VERSION 5.7 ;
  NOWIREEXTENSIONATPIN ON ;
  DIVIDERCHAR "/" ;
  BUSBITCHARS "[]" ;
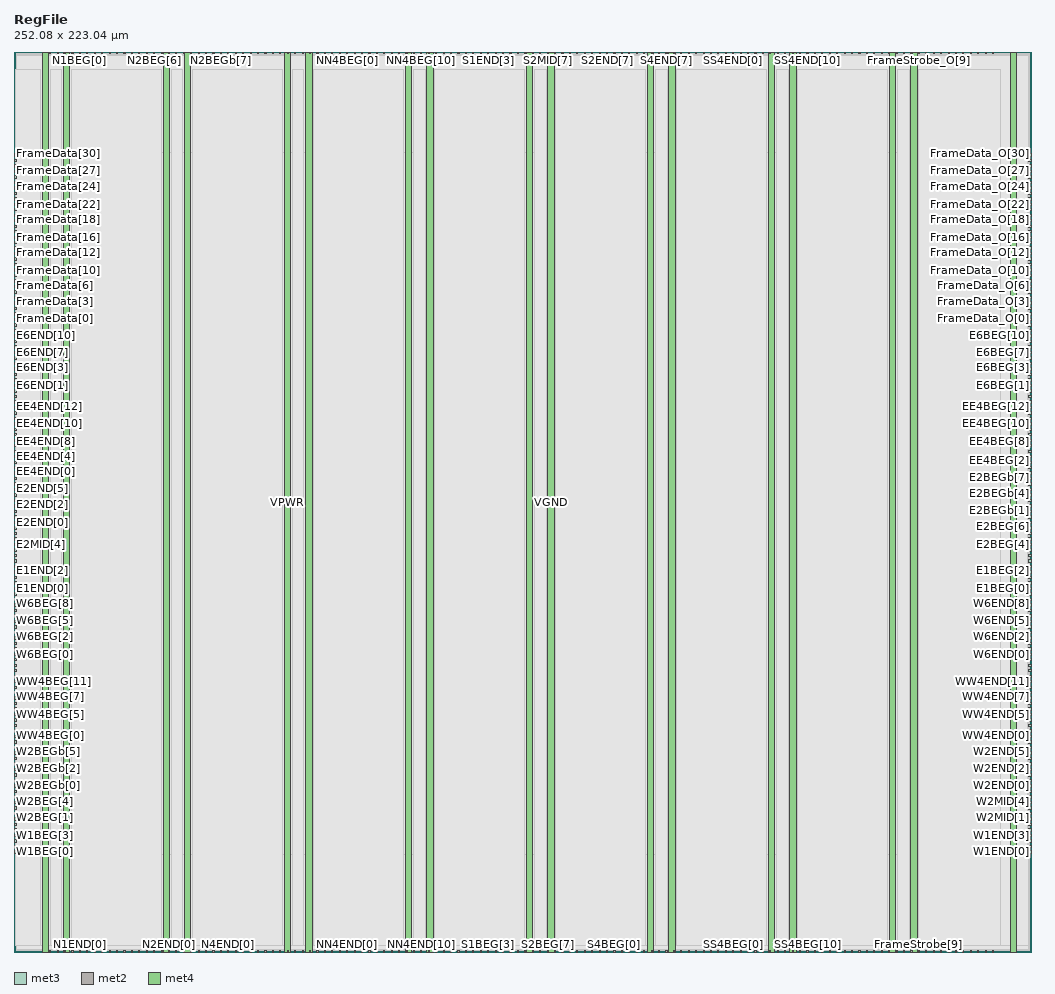
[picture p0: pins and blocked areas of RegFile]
MACRO RegFile
  CLASS BLOCK ;
  FOREIGN RegFile ;
  ORIGIN 0.000 0.000 ;
  SIZE 252.080 BY 223.040 ;
  PIN E1BEG[0]
    DIRECTION OUTPUT ;
    USE SIGNAL ;
    ANTENNADIFFAREA 0.702900 ;
    PORT
      LAYER met3 ;
        RECT 251.480 89.800 252.080 90.400 ;
    END
  END E1BEG[0]
  PIN E1BEG[1]
    DIRECTION OUTPUT ;
    USE SIGNAL ;
    ANTENNADIFFAREA 0.702900 ;
    PORT
      LAYER met3 ;
        RECT 251.480 91.160 252.080 91.760 ;
    END
  END E1BEG[1]
  PIN E1BEG[2]
    DIRECTION OUTPUT ;
    USE SIGNAL ;
    ANTENNADIFFAREA 0.702900 ;
    PORT
      LAYER met3 ;
        RECT 251.480 92.520 252.080 93.120 ;
    END
  END E1BEG[2]
  PIN E1BEG[3]
    DIRECTION OUTPUT ;
    USE SIGNAL ;
    ANTENNADIFFAREA 0.702900 ;
    PORT
      LAYER met3 ;
        RECT 251.480 93.880 252.080 94.480 ;
    END
  END E1BEG[3]
  PIN E1END[0]
    DIRECTION INPUT ;
    USE SIGNAL ;
    ANTENNAGATEAREA 1.398000 ;
    PORT
      LAYER met3 ;
        RECT 0.000 89.800 0.600 90.400 ;
    END
  END E1END[0]
  PIN E1END[1]
    DIRECTION INPUT ;
    USE SIGNAL ;
    ANTENNAGATEAREA 1.431000 ;
    PORT
      LAYER met3 ;
        RECT 0.000 91.160 0.600 91.760 ;
    END
  END E1END[1]
  PIN E1END[2]
    DIRECTION INPUT ;
    USE SIGNAL ;
    ANTENNAGATEAREA 2.117700 ;
    ANTENNADIFFAREA 0.434700 ;
    PORT
      LAYER met3 ;
        RECT 0.000 92.520 0.600 93.120 ;
    END
  END E1END[2]
  PIN E1END[3]
    DIRECTION INPUT ;
    USE SIGNAL ;
    ANTENNAGATEAREA 2.618400 ;
    ANTENNADIFFAREA 0.869400 ;
    PORT
      LAYER met3 ;
        RECT 0.000 93.880 0.600 94.480 ;
    END
  END E1END[3]
  PIN E2BEG[0]
    DIRECTION OUTPUT ;
    USE SIGNAL ;
    ANTENNADIFFAREA 0.702900 ;
    PORT
      LAYER met3 ;
        RECT 251.480 95.240 252.080 95.840 ;
    END
  END E2BEG[0]
  PIN E2BEG[1]
    DIRECTION OUTPUT ;
    USE SIGNAL ;
    ANTENNADIFFAREA 0.702900 ;
    PORT
      LAYER met3 ;
        RECT 251.480 96.600 252.080 97.200 ;
    END
  END E2BEG[1]
  PIN E2BEG[2]
    DIRECTION OUTPUT ;
    USE SIGNAL ;
    ANTENNADIFFAREA 0.702900 ;
    PORT
      LAYER met3 ;
        RECT 251.480 97.960 252.080 98.560 ;
    END
  END E2BEG[2]
  PIN E2BEG[3]
    DIRECTION OUTPUT ;
    USE SIGNAL ;
    ANTENNADIFFAREA 0.702900 ;
    PORT
      LAYER met3 ;
        RECT 251.480 99.320 252.080 99.920 ;
    END
  END E2BEG[3]
  PIN E2BEG[4]
    DIRECTION OUTPUT ;
    USE SIGNAL ;
    ANTENNADIFFAREA 0.702900 ;
    PORT
      LAYER met3 ;
        RECT 251.480 100.680 252.080 101.280 ;
    END
  END E2BEG[4]
  PIN E2BEG[5]
    DIRECTION OUTPUT ;
    USE SIGNAL ;
    ANTENNADIFFAREA 0.702900 ;
    PORT
      LAYER met3 ;
        RECT 251.480 102.040 252.080 102.640 ;
    END
  END E2BEG[5]
  PIN E2BEG[6]
    DIRECTION OUTPUT ;
    USE SIGNAL ;
    ANTENNADIFFAREA 0.702900 ;
    PORT
      LAYER met3 ;
        RECT 251.480 103.400 252.080 104.000 ;
    END
  END E2BEG[6]
  PIN E2BEG[7]
    DIRECTION OUTPUT ;
    USE SIGNAL ;
    ANTENNADIFFAREA 0.702900 ;
    PORT
      LAYER met3 ;
        RECT 251.480 104.760 252.080 105.360 ;
    END
  END E2BEG[7]
  PIN E2BEGb[0]
    DIRECTION OUTPUT ;
    USE SIGNAL ;
    ANTENNADIFFAREA 0.702900 ;
    PORT
      LAYER met3 ;
        RECT 251.480 106.120 252.080 106.720 ;
    END
  END E2BEGb[0]
  PIN E2BEGb[1]
    DIRECTION OUTPUT ;
    USE SIGNAL ;
    ANTENNADIFFAREA 0.702900 ;
    PORT
      LAYER met3 ;
        RECT 251.480 107.480 252.080 108.080 ;
    END
  END E2BEGb[1]
  PIN E2BEGb[2]
    DIRECTION OUTPUT ;
    USE SIGNAL ;
    ANTENNADIFFAREA 0.702900 ;
    PORT
      LAYER met3 ;
        RECT 251.480 108.840 252.080 109.440 ;
    END
  END E2BEGb[2]
  PIN E2BEGb[3]
    DIRECTION OUTPUT ;
    USE SIGNAL ;
    ANTENNADIFFAREA 0.702900 ;
    PORT
      LAYER met3 ;
        RECT 251.480 110.200 252.080 110.800 ;
    END
  END E2BEGb[3]
  PIN E2BEGb[4]
    DIRECTION OUTPUT ;
    USE SIGNAL ;
    ANTENNADIFFAREA 0.702900 ;
    PORT
      LAYER met3 ;
        RECT 251.480 111.560 252.080 112.160 ;
    END
  END E2BEGb[4]
  PIN E2BEGb[5]
    DIRECTION OUTPUT ;
    USE SIGNAL ;
    ANTENNADIFFAREA 0.702900 ;
    PORT
      LAYER met3 ;
        RECT 251.480 112.920 252.080 113.520 ;
    END
  END E2BEGb[5]
  PIN E2BEGb[6]
    DIRECTION OUTPUT ;
    USE SIGNAL ;
    ANTENNADIFFAREA 0.702900 ;
    PORT
      LAYER met3 ;
        RECT 251.480 114.280 252.080 114.880 ;
    END
  END E2BEGb[6]
  PIN E2BEGb[7]
    DIRECTION OUTPUT ;
    USE SIGNAL ;
    ANTENNADIFFAREA 0.702900 ;
    PORT
      LAYER met3 ;
        RECT 251.480 115.640 252.080 116.240 ;
    END
  END E2BEGb[7]
  PIN E2END[0]
    DIRECTION INPUT ;
    USE SIGNAL ;
    ANTENNAGATEAREA 1.664400 ;
    ANTENNADIFFAREA 0.869400 ;
    PORT
      LAYER met3 ;
        RECT 0.000 106.120 0.600 106.720 ;
    END
  END E2END[0]
  PIN E2END[1]
    DIRECTION INPUT ;
    USE SIGNAL ;
    ANTENNAGATEAREA 0.795000 ;
    PORT
      LAYER met3 ;
        RECT 0.000 107.480 0.600 108.080 ;
    END
  END E2END[1]
  PIN E2END[2]
    DIRECTION INPUT ;
    USE SIGNAL ;
    ANTENNAGATEAREA 2.108400 ;
    ANTENNADIFFAREA 0.869400 ;
    PORT
      LAYER met3 ;
        RECT 0.000 108.840 0.600 109.440 ;
    END
  END E2END[2]
  PIN E2END[3]
    DIRECTION INPUT ;
    USE SIGNAL ;
    ANTENNAGATEAREA 1.272000 ;
    PORT
      LAYER met3 ;
        RECT 0.000 110.200 0.600 110.800 ;
    END
  END E2END[3]
  PIN E2END[4]
    DIRECTION INPUT ;
    USE SIGNAL ;
    ANTENNAGATEAREA 0.795000 ;
    PORT
      LAYER met3 ;
        RECT 0.000 111.560 0.600 112.160 ;
    END
  END E2END[4]
  PIN E2END[5]
    DIRECTION INPUT ;
    USE SIGNAL ;
    ANTENNAGATEAREA 0.954000 ;
    PORT
      LAYER met3 ;
        RECT 0.000 112.920 0.600 113.520 ;
    END
  END E2END[5]
  PIN E2END[6]
    DIRECTION INPUT ;
    USE SIGNAL ;
    ANTENNAGATEAREA 1.823400 ;
    ANTENNADIFFAREA 0.869400 ;
    PORT
      LAYER met3 ;
        RECT 0.000 114.280 0.600 114.880 ;
    END
  END E2END[6]
  PIN E2END[7]
    DIRECTION INPUT ;
    USE SIGNAL ;
    ANTENNAGATEAREA 1.664400 ;
    ANTENNADIFFAREA 0.869400 ;
    PORT
      LAYER met3 ;
        RECT 0.000 115.640 0.600 116.240 ;
    END
  END E2END[7]
  PIN E2MID[0]
    DIRECTION INPUT ;
    USE SIGNAL ;
    ANTENNAGATEAREA 1.907100 ;
    ANTENNADIFFAREA 1.304100 ;
    PORT
      LAYER met3 ;
        RECT 0.000 95.240 0.600 95.840 ;
    END
  END E2MID[0]
  PIN E2MID[1]
    DIRECTION INPUT ;
    USE SIGNAL ;
    ANTENNAGATEAREA 0.696000 ;
    PORT
      LAYER met3 ;
        RECT 0.000 96.600 0.600 97.200 ;
    END
  END E2MID[1]
  PIN E2MID[2]
    DIRECTION INPUT ;
    USE SIGNAL ;
    ANTENNAGATEAREA 0.724500 ;
    PORT
      LAYER met3 ;
        RECT 0.000 97.960 0.600 98.560 ;
    END
  END E2MID[2]
  PIN E2MID[3]
    DIRECTION INPUT ;
    USE SIGNAL ;
    ANTENNAGATEAREA 1.229700 ;
    ANTENNADIFFAREA 0.434700 ;
    PORT
      LAYER met3 ;
        RECT 0.000 99.320 0.600 99.920 ;
    END
  END E2MID[3]
  PIN E2MID[4]
    DIRECTION INPUT ;
    USE SIGNAL ;
    ANTENNAGATEAREA 2.374800 ;
    ANTENNADIFFAREA 1.738800 ;
    PORT
      LAYER met3 ;
        RECT 0.000 100.680 0.600 101.280 ;
    END
  END E2MID[4]
  PIN E2MID[5]
    DIRECTION INPUT ;
    USE SIGNAL ;
    ANTENNAGATEAREA 2.968500 ;
    ANTENNADIFFAREA 2.173500 ;
    PORT
      LAYER met3 ;
        RECT 0.000 102.040 0.600 102.640 ;
    END
  END E2MID[5]
  PIN E2MID[6]
    DIRECTION INPUT ;
    USE SIGNAL ;
    ANTENNAGATEAREA 1.439400 ;
    ANTENNADIFFAREA 0.869400 ;
    PORT
      LAYER met3 ;
        RECT 0.000 103.400 0.600 104.000 ;
    END
  END E2MID[6]
  PIN E2MID[7]
    DIRECTION INPUT ;
    USE SIGNAL ;
    ANTENNAGATEAREA 2.869500 ;
    ANTENNADIFFAREA 2.173500 ;
    PORT
      LAYER met3 ;
        RECT 0.000 104.760 0.600 105.360 ;
    END
  END E2MID[7]
  PIN E6BEG[0]
    DIRECTION OUTPUT ;
    USE SIGNAL ;
    ANTENNADIFFAREA 0.702900 ;
    PORT
      LAYER met3 ;
        RECT 251.480 138.760 252.080 139.360 ;
    END
  END E6BEG[0]
  PIN E6BEG[10]
    DIRECTION OUTPUT ;
    USE SIGNAL ;
    ANTENNADIFFAREA 0.702900 ;
    PORT
      LAYER met3 ;
        RECT 251.480 152.360 252.080 152.960 ;
    END
  END E6BEG[10]
  PIN E6BEG[11]
    DIRECTION OUTPUT ;
    USE SIGNAL ;
    ANTENNADIFFAREA 0.702900 ;
    PORT
      LAYER met3 ;
        RECT 251.480 153.720 252.080 154.320 ;
    END
  END E6BEG[11]
  PIN E6BEG[1]
    DIRECTION OUTPUT ;
    USE SIGNAL ;
    ANTENNADIFFAREA 0.702900 ;
    PORT
      LAYER met3 ;
        RECT 251.480 140.120 252.080 140.720 ;
    END
  END E6BEG[1]
  PIN E6BEG[2]
    DIRECTION OUTPUT ;
    USE SIGNAL ;
    ANTENNADIFFAREA 0.702900 ;
    PORT
      LAYER met3 ;
        RECT 251.480 141.480 252.080 142.080 ;
    END
  END E6BEG[2]
  PIN E6BEG[3]
    DIRECTION OUTPUT ;
    USE SIGNAL ;
    ANTENNADIFFAREA 0.702900 ;
    PORT
      LAYER met3 ;
        RECT 251.480 142.840 252.080 143.440 ;
    END
  END E6BEG[3]
  PIN E6BEG[4]
    DIRECTION OUTPUT ;
    USE SIGNAL ;
    ANTENNADIFFAREA 0.702900 ;
    PORT
      LAYER met3 ;
        RECT 251.480 144.200 252.080 144.800 ;
    END
  END E6BEG[4]
  PIN E6BEG[5]
    DIRECTION OUTPUT ;
    USE SIGNAL ;
    ANTENNADIFFAREA 0.702900 ;
    PORT
      LAYER met3 ;
        RECT 251.480 145.560 252.080 146.160 ;
    END
  END E6BEG[5]
  PIN E6BEG[6]
    DIRECTION OUTPUT ;
    USE SIGNAL ;
    ANTENNADIFFAREA 0.702900 ;
    PORT
      LAYER met3 ;
        RECT 251.480 146.920 252.080 147.520 ;
    END
  END E6BEG[6]
  PIN E6BEG[7]
    DIRECTION OUTPUT ;
    USE SIGNAL ;
    ANTENNADIFFAREA 0.702900 ;
    PORT
      LAYER met3 ;
        RECT 251.480 148.280 252.080 148.880 ;
    END
  END E6BEG[7]
  PIN E6BEG[8]
    DIRECTION OUTPUT ;
    USE SIGNAL ;
    ANTENNADIFFAREA 0.702900 ;
    PORT
      LAYER met3 ;
        RECT 251.480 149.640 252.080 150.240 ;
    END
  END E6BEG[8]
  PIN E6BEG[9]
    DIRECTION OUTPUT ;
    USE SIGNAL ;
    ANTENNADIFFAREA 0.702900 ;
    PORT
      LAYER met3 ;
        RECT 251.480 151.000 252.080 151.600 ;
    END
  END E6BEG[9]
  PIN E6END[0]
    DIRECTION INPUT ;
    USE SIGNAL ;
    ANTENNAGATEAREA 1.875000 ;
    PORT
      LAYER met3 ;
        RECT 0.000 138.760 0.600 139.360 ;
    END
  END E6END[0]
  PIN E6END[10]
    DIRECTION INPUT ;
    USE SIGNAL ;
    ANTENNAGATEAREA 0.159000 ;
    PORT
      LAYER met3 ;
        RECT 0.000 152.360 0.600 152.960 ;
    END
  END E6END[10]
  PIN E6END[11]
    DIRECTION INPUT ;
    USE SIGNAL ;
    ANTENNAGATEAREA 0.159000 ;
    PORT
      LAYER met3 ;
        RECT 0.000 153.720 0.600 154.320 ;
    END
  END E6END[11]
  PIN E6END[1]
    DIRECTION INPUT ;
    USE SIGNAL ;
    ANTENNAGATEAREA 1.875000 ;
    PORT
      LAYER met3 ;
        RECT 0.000 140.120 0.600 140.720 ;
    END
  END E6END[1]
  PIN E6END[2]
    DIRECTION INPUT ;
    USE SIGNAL ;
    ANTENNAGATEAREA 0.159000 ;
    PORT
      LAYER met3 ;
        RECT 0.000 141.480 0.600 142.080 ;
    END
  END E6END[2]
  PIN E6END[3]
    DIRECTION INPUT ;
    USE SIGNAL ;
    ANTENNAGATEAREA 0.159000 ;
    PORT
      LAYER met3 ;
        RECT 0.000 142.840 0.600 143.440 ;
    END
  END E6END[3]
  PIN E6END[4]
    DIRECTION INPUT ;
    USE SIGNAL ;
    ANTENNAGATEAREA 0.159000 ;
    PORT
      LAYER met3 ;
        RECT 0.000 144.200 0.600 144.800 ;
    END
  END E6END[4]
  PIN E6END[5]
    DIRECTION INPUT ;
    USE SIGNAL ;
    ANTENNAGATEAREA 0.159000 ;
    PORT
      LAYER met3 ;
        RECT 0.000 145.560 0.600 146.160 ;
    END
  END E6END[5]
  PIN E6END[6]
    DIRECTION INPUT ;
    USE SIGNAL ;
    ANTENNAGATEAREA 0.159000 ;
    PORT
      LAYER met3 ;
        RECT 0.000 146.920 0.600 147.520 ;
    END
  END E6END[6]
  PIN E6END[7]
    DIRECTION INPUT ;
    USE SIGNAL ;
    ANTENNAGATEAREA 0.159000 ;
    PORT
      LAYER met3 ;
        RECT 0.000 148.280 0.600 148.880 ;
    END
  END E6END[7]
  PIN E6END[8]
    DIRECTION INPUT ;
    USE SIGNAL ;
    ANTENNAGATEAREA 0.159000 ;
    PORT
      LAYER met3 ;
        RECT 0.000 149.640 0.600 150.240 ;
    END
  END E6END[8]
  PIN E6END[9]
    DIRECTION INPUT ;
    USE SIGNAL ;
    ANTENNAGATEAREA 0.159000 ;
    PORT
      LAYER met3 ;
        RECT 0.000 151.000 0.600 151.600 ;
    END
  END E6END[9]
  PIN EE4BEG[0]
    DIRECTION OUTPUT ;
    USE SIGNAL ;
    ANTENNADIFFAREA 0.702900 ;
    PORT
      LAYER met3 ;
        RECT 251.480 117.000 252.080 117.600 ;
    END
  END EE4BEG[0]
  PIN EE4BEG[10]
    DIRECTION OUTPUT ;
    USE SIGNAL ;
    ANTENNADIFFAREA 0.702900 ;
    PORT
      LAYER met3 ;
        RECT 251.480 130.600 252.080 131.200 ;
    END
  END EE4BEG[10]
  PIN EE4BEG[11]
    DIRECTION OUTPUT ;
    USE SIGNAL ;
    ANTENNADIFFAREA 0.702900 ;
    PORT
      LAYER met3 ;
        RECT 251.480 131.960 252.080 132.560 ;
    END
  END EE4BEG[11]
  PIN EE4BEG[12]
    DIRECTION OUTPUT ;
    USE SIGNAL ;
    ANTENNADIFFAREA 0.702900 ;
    PORT
      LAYER met3 ;
        RECT 251.480 133.320 252.080 133.920 ;
    END
  END EE4BEG[12]
  PIN EE4BEG[13]
    DIRECTION OUTPUT ;
    USE SIGNAL ;
    ANTENNADIFFAREA 0.702900 ;
    PORT
      LAYER met3 ;
        RECT 251.480 134.680 252.080 135.280 ;
    END
  END EE4BEG[13]
  PIN EE4BEG[14]
    DIRECTION OUTPUT ;
    USE SIGNAL ;
    ANTENNADIFFAREA 0.702900 ;
    PORT
      LAYER met3 ;
        RECT 251.480 136.040 252.080 136.640 ;
    END
  END EE4BEG[14]
  PIN EE4BEG[15]
    DIRECTION OUTPUT ;
    USE SIGNAL ;
    ANTENNADIFFAREA 0.702900 ;
    PORT
      LAYER met3 ;
        RECT 251.480 137.400 252.080 138.000 ;
    END
  END EE4BEG[15]
  PIN EE4BEG[1]
    DIRECTION OUTPUT ;
    USE SIGNAL ;
    ANTENNADIFFAREA 0.702900 ;
    PORT
      LAYER met3 ;
        RECT 251.480 118.360 252.080 118.960 ;
    END
  END EE4BEG[1]
  PIN EE4BEG[2]
    DIRECTION OUTPUT ;
    USE SIGNAL ;
    ANTENNADIFFAREA 0.702900 ;
    PORT
      LAYER met3 ;
        RECT 251.480 119.720 252.080 120.320 ;
    END
  END EE4BEG[2]
  PIN EE4BEG[3]
    DIRECTION OUTPUT ;
    USE SIGNAL ;
    ANTENNADIFFAREA 0.702900 ;
    PORT
      LAYER met3 ;
        RECT 251.480 121.080 252.080 121.680 ;
    END
  END EE4BEG[3]
  PIN EE4BEG[4]
    DIRECTION OUTPUT ;
    USE SIGNAL ;
    ANTENNADIFFAREA 0.702900 ;
    PORT
      LAYER met3 ;
        RECT 251.480 122.440 252.080 123.040 ;
    END
  END EE4BEG[4]
  PIN EE4BEG[5]
    DIRECTION OUTPUT ;
    USE SIGNAL ;
    ANTENNADIFFAREA 0.702900 ;
    PORT
      LAYER met3 ;
        RECT 251.480 123.800 252.080 124.400 ;
    END
  END EE4BEG[5]
  PIN EE4BEG[6]
    DIRECTION OUTPUT ;
    USE SIGNAL ;
    ANTENNADIFFAREA 0.702900 ;
    PORT
      LAYER met3 ;
        RECT 251.480 125.160 252.080 125.760 ;
    END
  END EE4BEG[6]
  PIN EE4BEG[7]
    DIRECTION OUTPUT ;
    USE SIGNAL ;
    ANTENNADIFFAREA 0.702900 ;
    PORT
      LAYER met3 ;
        RECT 251.480 126.520 252.080 127.120 ;
    END
  END EE4BEG[7]
  PIN EE4BEG[8]
    DIRECTION OUTPUT ;
    USE SIGNAL ;
    ANTENNADIFFAREA 0.702900 ;
    PORT
      LAYER met3 ;
        RECT 251.480 127.880 252.080 128.480 ;
    END
  END EE4BEG[8]
  PIN EE4BEG[9]
    DIRECTION OUTPUT ;
    USE SIGNAL ;
    ANTENNADIFFAREA 0.702900 ;
    PORT
      LAYER met3 ;
        RECT 251.480 129.240 252.080 129.840 ;
    END
  END EE4BEG[9]
  PIN EE4END[0]
    DIRECTION INPUT ;
    USE SIGNAL ;
    ANTENNAGATEAREA 2.374800 ;
    ANTENNADIFFAREA 1.738800 ;
    PORT
      LAYER met3 ;
        RECT 0.000 117.000 0.600 117.600 ;
    END
  END EE4END[0]
  PIN EE4END[10]
    DIRECTION INPUT ;
    USE SIGNAL ;
    ANTENNAGATEAREA 0.159000 ;
    PORT
      LAYER met3 ;
        RECT 0.000 130.600 0.600 131.200 ;
    END
  END EE4END[10]
  PIN EE4END[11]
    DIRECTION INPUT ;
    USE SIGNAL ;
    ANTENNAGATEAREA 0.159000 ;
    PORT
      LAYER met3 ;
        RECT 0.000 131.960 0.600 132.560 ;
    END
  END EE4END[11]
  PIN EE4END[12]
    DIRECTION INPUT ;
    USE SIGNAL ;
    ANTENNAGATEAREA 0.159000 ;
    PORT
      LAYER met3 ;
        RECT 0.000 133.320 0.600 133.920 ;
    END
  END EE4END[12]
  PIN EE4END[13]
    DIRECTION INPUT ;
    USE SIGNAL ;
    ANTENNAGATEAREA 0.159000 ;
    PORT
      LAYER met3 ;
        RECT 0.000 134.680 0.600 135.280 ;
    END
  END EE4END[13]
  PIN EE4END[14]
    DIRECTION INPUT ;
    USE SIGNAL ;
    ANTENNAGATEAREA 0.159000 ;
    PORT
      LAYER met3 ;
        RECT 0.000 136.040 0.600 136.640 ;
    END
  END EE4END[14]
  PIN EE4END[15]
    DIRECTION INPUT ;
    USE SIGNAL ;
    ANTENNAGATEAREA 0.159000 ;
    PORT
      LAYER met3 ;
        RECT 0.000 137.400 0.600 138.000 ;
    END
  END EE4END[15]
  PIN EE4END[1]
    DIRECTION INPUT ;
    USE SIGNAL ;
    ANTENNAGATEAREA 1.505400 ;
    ANTENNADIFFAREA 0.869400 ;
    PORT
      LAYER met3 ;
        RECT 0.000 118.360 0.600 118.960 ;
    END
  END EE4END[1]
  PIN EE4END[2]
    DIRECTION INPUT ;
    USE SIGNAL ;
    ANTENNAGATEAREA 1.070700 ;
    ANTENNADIFFAREA 0.434700 ;
    PORT
      LAYER met3 ;
        RECT 0.000 119.720 0.600 120.320 ;
    END
  END EE4END[2]
  PIN EE4END[3]
    DIRECTION INPUT ;
    USE SIGNAL ;
    ANTENNAGATEAREA 1.406700 ;
    ANTENNADIFFAREA 0.434700 ;
    PORT
      LAYER met3 ;
        RECT 0.000 121.080 0.600 121.680 ;
    END
  END EE4END[3]
  PIN EE4END[4]
    DIRECTION INPUT ;
    USE SIGNAL ;
    ANTENNAGATEAREA 0.159000 ;
    PORT
      LAYER met3 ;
        RECT 0.000 122.440 0.600 123.040 ;
    END
  END EE4END[4]
  PIN EE4END[5]
    DIRECTION INPUT ;
    USE SIGNAL ;
    ANTENNAGATEAREA 0.159000 ;
    PORT
      LAYER met3 ;
        RECT 0.000 123.800 0.600 124.400 ;
    END
  END EE4END[5]
  PIN EE4END[6]
    DIRECTION INPUT ;
    USE SIGNAL ;
    ANTENNAGATEAREA 0.159000 ;
    PORT
      LAYER met3 ;
        RECT 0.000 125.160 0.600 125.760 ;
    END
  END EE4END[6]
  PIN EE4END[7]
    DIRECTION INPUT ;
    USE SIGNAL ;
    ANTENNAGATEAREA 0.159000 ;
    PORT
      LAYER met3 ;
        RECT 0.000 126.520 0.600 127.120 ;
    END
  END EE4END[7]
  PIN EE4END[8]
    DIRECTION INPUT ;
    USE SIGNAL ;
    ANTENNAGATEAREA 0.159000 ;
    PORT
      LAYER met3 ;
        RECT 0.000 127.880 0.600 128.480 ;
    END
  END EE4END[8]
  PIN EE4END[9]
    DIRECTION INPUT ;
    USE SIGNAL ;
    ANTENNAGATEAREA 0.159000 ;
    PORT
      LAYER met3 ;
        RECT 0.000 129.240 0.600 129.840 ;
    END
  END EE4END[9]
  PIN FrameData[0]
    DIRECTION INPUT ;
    USE SIGNAL ;
    ANTENNAGATEAREA 2.660700 ;
    ANTENNADIFFAREA 0.434700 ;
    PORT
      LAYER met3 ;
        RECT 0.000 155.080 0.600 155.680 ;
    END
  END FrameData[0]
  PIN FrameData[10]
    DIRECTION INPUT ;
    USE SIGNAL ;
    ANTENNAGATEAREA 2.660700 ;
    ANTENNADIFFAREA 0.434700 ;
    PORT
      LAYER met3 ;
        RECT 0.000 168.680 0.600 169.280 ;
    END
  END FrameData[10]
  PIN FrameData[11]
    DIRECTION INPUT ;
    USE SIGNAL ;
    ANTENNAGATEAREA 2.660700 ;
    ANTENNADIFFAREA 0.434700 ;
    PORT
      LAYER met3 ;
        RECT 0.000 170.040 0.600 170.640 ;
    END
  END FrameData[11]
  PIN FrameData[12]
    DIRECTION INPUT ;
    USE SIGNAL ;
    ANTENNAGATEAREA 2.226000 ;
    PORT
      LAYER met3 ;
        RECT 0.000 171.400 0.600 172.000 ;
    END
  END FrameData[12]
  PIN FrameData[13]
    DIRECTION INPUT ;
    USE SIGNAL ;
    ANTENNAGATEAREA 2.226000 ;
    PORT
      LAYER met3 ;
        RECT 0.000 172.760 0.600 173.360 ;
    END
  END FrameData[13]
  PIN FrameData[14]
    DIRECTION INPUT ;
    USE SIGNAL ;
    ANTENNAGATEAREA 2.226000 ;
    PORT
      LAYER met3 ;
        RECT 0.000 174.120 0.600 174.720 ;
    END
  END FrameData[14]
  PIN FrameData[15]
    DIRECTION INPUT ;
    USE SIGNAL ;
    ANTENNAGATEAREA 2.226000 ;
    PORT
      LAYER met3 ;
        RECT 0.000 175.480 0.600 176.080 ;
    END
  END FrameData[15]
  PIN FrameData[16]
    DIRECTION INPUT ;
    USE SIGNAL ;
    ANTENNAGATEAREA 2.226000 ;
    PORT
      LAYER met3 ;
        RECT 0.000 176.840 0.600 177.440 ;
    END
  END FrameData[16]
  PIN FrameData[17]
    DIRECTION INPUT ;
    USE SIGNAL ;
    ANTENNAGATEAREA 2.226000 ;
    PORT
      LAYER met3 ;
        RECT 0.000 178.200 0.600 178.800 ;
    END
  END FrameData[17]
  PIN FrameData[18]
    DIRECTION INPUT ;
    USE SIGNAL ;
    ANTENNAGATEAREA 2.226000 ;
    PORT
      LAYER met3 ;
        RECT 0.000 179.560 0.600 180.160 ;
    END
  END FrameData[18]
  PIN FrameData[19]
    DIRECTION INPUT ;
    USE SIGNAL ;
    ANTENNAGATEAREA 2.385000 ;
    PORT
      LAYER met3 ;
        RECT 0.000 180.920 0.600 181.520 ;
    END
  END FrameData[19]
  PIN FrameData[1]
    DIRECTION INPUT ;
    USE SIGNAL ;
    ANTENNAGATEAREA 2.226000 ;
    PORT
      LAYER met3 ;
        RECT 0.000 156.440 0.600 157.040 ;
    END
  END FrameData[1]
  PIN FrameData[20]
    DIRECTION INPUT ;
    USE SIGNAL ;
    ANTENNAGATEAREA 2.385000 ;
    PORT
      LAYER met3 ;
        RECT 0.000 182.280 0.600 182.880 ;
    END
  END FrameData[20]
  PIN FrameData[21]
    DIRECTION INPUT ;
    USE SIGNAL ;
    ANTENNAGATEAREA 2.385000 ;
    PORT
      LAYER met3 ;
        RECT 0.000 183.640 0.600 184.240 ;
    END
  END FrameData[21]
  PIN FrameData[22]
    DIRECTION INPUT ;
    USE SIGNAL ;
    ANTENNAGATEAREA 4.558500 ;
    ANTENNADIFFAREA 2.173500 ;
    PORT
      LAYER met3 ;
        RECT 0.000 185.000 0.600 185.600 ;
    END
  END FrameData[22]
  PIN FrameData[23]
    DIRECTION INPUT ;
    USE SIGNAL ;
    ANTENNAGATEAREA 2.385000 ;
    PORT
      LAYER met3 ;
        RECT 0.000 186.360 0.600 186.960 ;
    END
  END FrameData[23]
  PIN FrameData[24]
    DIRECTION INPUT ;
    USE SIGNAL ;
    ANTENNAGATEAREA 2.385000 ;
    PORT
      LAYER met3 ;
        RECT 0.000 187.720 0.600 188.320 ;
    END
  END FrameData[24]
  PIN FrameData[25]
    DIRECTION INPUT ;
    USE SIGNAL ;
    ANTENNAGATEAREA 2.385000 ;
    PORT
      LAYER met3 ;
        RECT 0.000 189.080 0.600 189.680 ;
    END
  END FrameData[25]
  PIN FrameData[26]
    DIRECTION INPUT ;
    USE SIGNAL ;
    ANTENNAGATEAREA 2.385000 ;
    PORT
      LAYER met3 ;
        RECT 0.000 190.440 0.600 191.040 ;
    END
  END FrameData[26]
  PIN FrameData[27]
    DIRECTION INPUT ;
    USE SIGNAL ;
    ANTENNAGATEAREA 2.385000 ;
    PORT
      LAYER met3 ;
        RECT 0.000 191.800 0.600 192.400 ;
    END
  END FrameData[27]
  PIN FrameData[28]
    DIRECTION INPUT ;
    USE SIGNAL ;
    ANTENNAGATEAREA 2.819700 ;
    ANTENNADIFFAREA 0.434700 ;
    PORT
      LAYER met3 ;
        RECT 0.000 193.160 0.600 193.760 ;
    END
  END FrameData[28]
  PIN FrameData[29]
    DIRECTION INPUT ;
    USE SIGNAL ;
    ANTENNAGATEAREA 2.385000 ;
    PORT
      LAYER met3 ;
        RECT 0.000 194.520 0.600 195.120 ;
    END
  END FrameData[29]
  PIN FrameData[2]
    DIRECTION INPUT ;
    USE SIGNAL ;
    ANTENNAGATEAREA 2.226000 ;
    PORT
      LAYER met3 ;
        RECT 0.000 157.800 0.600 158.400 ;
    END
  END FrameData[2]
  PIN FrameData[30]
    DIRECTION INPUT ;
    USE SIGNAL ;
    ANTENNAGATEAREA 2.385000 ;
    PORT
      LAYER met3 ;
        RECT 0.000 195.880 0.600 196.480 ;
    END
  END FrameData[30]
  PIN FrameData[31]
    DIRECTION INPUT ;
    USE SIGNAL ;
    ANTENNAGATEAREA 2.385000 ;
    PORT
      LAYER met3 ;
        RECT 0.000 197.240 0.600 197.840 ;
    END
  END FrameData[31]
  PIN FrameData[3]
    DIRECTION INPUT ;
    USE SIGNAL ;
    ANTENNAGATEAREA 2.226000 ;
    PORT
      LAYER met3 ;
        RECT 0.000 159.160 0.600 159.760 ;
    END
  END FrameData[3]
  PIN FrameData[4]
    DIRECTION INPUT ;
    USE SIGNAL ;
    ANTENNAGATEAREA 2.226000 ;
    PORT
      LAYER met3 ;
        RECT 0.000 160.520 0.600 161.120 ;
    END
  END FrameData[4]
  PIN FrameData[5]
    DIRECTION INPUT ;
    USE SIGNAL ;
    ANTENNAGATEAREA 2.226000 ;
    PORT
      LAYER met3 ;
        RECT 0.000 161.880 0.600 162.480 ;
    END
  END FrameData[5]
  PIN FrameData[6]
    DIRECTION INPUT ;
    USE SIGNAL ;
    ANTENNAGATEAREA 2.226000 ;
    PORT
      LAYER met3 ;
        RECT 0.000 163.240 0.600 163.840 ;
    END
  END FrameData[6]
  PIN FrameData[7]
    DIRECTION INPUT ;
    USE SIGNAL ;
    ANTENNAGATEAREA 2.226000 ;
    PORT
      LAYER met3 ;
        RECT 0.000 164.600 0.600 165.200 ;
    END
  END FrameData[7]
  PIN FrameData[8]
    DIRECTION INPUT ;
    USE SIGNAL ;
    ANTENNAGATEAREA 2.226000 ;
    PORT
      LAYER met3 ;
        RECT 0.000 165.960 0.600 166.560 ;
    END
  END FrameData[8]
  PIN FrameData[9]
    DIRECTION INPUT ;
    USE SIGNAL ;
    ANTENNAGATEAREA 2.226000 ;
    PORT
      LAYER met3 ;
        RECT 0.000 167.320 0.600 167.920 ;
    END
  END FrameData[9]
  PIN FrameData_O[0]
    DIRECTION OUTPUT ;
    USE SIGNAL ;
    ANTENNADIFFAREA 0.702900 ;
    PORT
      LAYER met3 ;
        RECT 251.480 155.080 252.080 155.680 ;
    END
  END FrameData_O[0]
  PIN FrameData_O[10]
    DIRECTION OUTPUT ;
    USE SIGNAL ;
    ANTENNADIFFAREA 0.702900 ;
    PORT
      LAYER met3 ;
        RECT 251.480 168.680 252.080 169.280 ;
    END
  END FrameData_O[10]
  PIN FrameData_O[11]
    DIRECTION OUTPUT ;
    USE SIGNAL ;
    ANTENNADIFFAREA 0.702900 ;
    PORT
      LAYER met3 ;
        RECT 251.480 170.040 252.080 170.640 ;
    END
  END FrameData_O[11]
  PIN FrameData_O[12]
    DIRECTION OUTPUT ;
    USE SIGNAL ;
    ANTENNADIFFAREA 0.702900 ;
    PORT
      LAYER met3 ;
        RECT 251.480 171.400 252.080 172.000 ;
    END
  END FrameData_O[12]
  PIN FrameData_O[13]
    DIRECTION OUTPUT ;
    USE SIGNAL ;
    ANTENNADIFFAREA 0.702900 ;
    PORT
      LAYER met3 ;
        RECT 251.480 172.760 252.080 173.360 ;
    END
  END FrameData_O[13]
  PIN FrameData_O[14]
    DIRECTION OUTPUT ;
    USE SIGNAL ;
    ANTENNADIFFAREA 0.702900 ;
    PORT
      LAYER met3 ;
        RECT 251.480 174.120 252.080 174.720 ;
    END
  END FrameData_O[14]
  PIN FrameData_O[15]
    DIRECTION OUTPUT ;
    USE SIGNAL ;
    ANTENNADIFFAREA 0.702900 ;
    PORT
      LAYER met3 ;
        RECT 251.480 175.480 252.080 176.080 ;
    END
  END FrameData_O[15]
  PIN FrameData_O[16]
    DIRECTION OUTPUT ;
    USE SIGNAL ;
    ANTENNADIFFAREA 0.702900 ;
    PORT
      LAYER met3 ;
        RECT 251.480 176.840 252.080 177.440 ;
    END
  END FrameData_O[16]
  PIN FrameData_O[17]
    DIRECTION OUTPUT ;
    USE SIGNAL ;
    ANTENNADIFFAREA 0.702900 ;
    PORT
      LAYER met3 ;
        RECT 251.480 178.200 252.080 178.800 ;
    END
  END FrameData_O[17]
  PIN FrameData_O[18]
    DIRECTION OUTPUT ;
    USE SIGNAL ;
    ANTENNADIFFAREA 0.702900 ;
    PORT
      LAYER met3 ;
        RECT 251.480 179.560 252.080 180.160 ;
    END
  END FrameData_O[18]
  PIN FrameData_O[19]
    DIRECTION OUTPUT ;
    USE SIGNAL ;
    ANTENNADIFFAREA 0.702900 ;
    PORT
      LAYER met3 ;
        RECT 251.480 180.920 252.080 181.520 ;
    END
  END FrameData_O[19]
  PIN FrameData_O[1]
    DIRECTION OUTPUT ;
    USE SIGNAL ;
    ANTENNADIFFAREA 0.702900 ;
    PORT
      LAYER met3 ;
        RECT 251.480 156.440 252.080 157.040 ;
    END
  END FrameData_O[1]
  PIN FrameData_O[20]
    DIRECTION OUTPUT ;
    USE SIGNAL ;
    ANTENNADIFFAREA 0.702900 ;
    PORT
      LAYER met3 ;
        RECT 251.480 182.280 252.080 182.880 ;
    END
  END FrameData_O[20]
  PIN FrameData_O[21]
    DIRECTION OUTPUT ;
    USE SIGNAL ;
    ANTENNADIFFAREA 0.702900 ;
    PORT
      LAYER met3 ;
        RECT 251.480 183.640 252.080 184.240 ;
    END
  END FrameData_O[21]
  PIN FrameData_O[22]
    DIRECTION OUTPUT ;
    USE SIGNAL ;
    ANTENNADIFFAREA 0.702900 ;
    PORT
      LAYER met3 ;
        RECT 251.480 185.000 252.080 185.600 ;
    END
  END FrameData_O[22]
  PIN FrameData_O[23]
    DIRECTION OUTPUT ;
    USE SIGNAL ;
    ANTENNADIFFAREA 0.702900 ;
    PORT
      LAYER met3 ;
        RECT 251.480 186.360 252.080 186.960 ;
    END
  END FrameData_O[23]
  PIN FrameData_O[24]
    DIRECTION OUTPUT ;
    USE SIGNAL ;
    ANTENNADIFFAREA 0.702900 ;
    PORT
      LAYER met3 ;
        RECT 251.480 187.720 252.080 188.320 ;
    END
  END FrameData_O[24]
  PIN FrameData_O[25]
    DIRECTION OUTPUT ;
    USE SIGNAL ;
    ANTENNADIFFAREA 0.702900 ;
    PORT
      LAYER met3 ;
        RECT 251.480 189.080 252.080 189.680 ;
    END
  END FrameData_O[25]
  PIN FrameData_O[26]
    DIRECTION OUTPUT ;
    USE SIGNAL ;
    ANTENNADIFFAREA 0.702900 ;
    PORT
      LAYER met3 ;
        RECT 251.480 190.440 252.080 191.040 ;
    END
  END FrameData_O[26]
  PIN FrameData_O[27]
    DIRECTION OUTPUT ;
    USE SIGNAL ;
    ANTENNADIFFAREA 0.702900 ;
    PORT
      LAYER met3 ;
        RECT 251.480 191.800 252.080 192.400 ;
    END
  END FrameData_O[27]
  PIN FrameData_O[28]
    DIRECTION OUTPUT ;
    USE SIGNAL ;
    ANTENNADIFFAREA 0.702900 ;
    PORT
      LAYER met3 ;
        RECT 251.480 193.160 252.080 193.760 ;
    END
  END FrameData_O[28]
  PIN FrameData_O[29]
    DIRECTION OUTPUT ;
    USE SIGNAL ;
    ANTENNADIFFAREA 0.702900 ;
    PORT
      LAYER met3 ;
        RECT 251.480 194.520 252.080 195.120 ;
    END
  END FrameData_O[29]
  PIN FrameData_O[2]
    DIRECTION OUTPUT ;
    USE SIGNAL ;
    ANTENNADIFFAREA 0.702900 ;
    PORT
      LAYER met3 ;
        RECT 251.480 157.800 252.080 158.400 ;
    END
  END FrameData_O[2]
  PIN FrameData_O[30]
    DIRECTION OUTPUT ;
    USE SIGNAL ;
    ANTENNADIFFAREA 0.702900 ;
    PORT
      LAYER met3 ;
        RECT 251.480 195.880 252.080 196.480 ;
    END
  END FrameData_O[30]
  PIN FrameData_O[31]
    DIRECTION OUTPUT ;
    USE SIGNAL ;
    ANTENNADIFFAREA 0.702900 ;
    PORT
      LAYER met3 ;
        RECT 251.480 197.240 252.080 197.840 ;
    END
  END FrameData_O[31]
  PIN FrameData_O[3]
    DIRECTION OUTPUT ;
    USE SIGNAL ;
    ANTENNADIFFAREA 0.702900 ;
    PORT
      LAYER met3 ;
        RECT 251.480 159.160 252.080 159.760 ;
    END
  END FrameData_O[3]
  PIN FrameData_O[4]
    DIRECTION OUTPUT ;
    USE SIGNAL ;
    ANTENNADIFFAREA 0.702900 ;
    PORT
      LAYER met3 ;
        RECT 251.480 160.520 252.080 161.120 ;
    END
  END FrameData_O[4]
  PIN FrameData_O[5]
    DIRECTION OUTPUT ;
    USE SIGNAL ;
    ANTENNADIFFAREA 0.702900 ;
    PORT
      LAYER met3 ;
        RECT 251.480 161.880 252.080 162.480 ;
    END
  END FrameData_O[5]
  PIN FrameData_O[6]
    DIRECTION OUTPUT ;
    USE SIGNAL ;
    ANTENNADIFFAREA 0.702900 ;
    PORT
      LAYER met3 ;
        RECT 251.480 163.240 252.080 163.840 ;
    END
  END FrameData_O[6]
  PIN FrameData_O[7]
    DIRECTION OUTPUT ;
    USE SIGNAL ;
    ANTENNADIFFAREA 0.702900 ;
    PORT
      LAYER met3 ;
        RECT 251.480 164.600 252.080 165.200 ;
    END
  END FrameData_O[7]
  PIN FrameData_O[8]
    DIRECTION OUTPUT ;
    USE SIGNAL ;
    ANTENNADIFFAREA 0.702900 ;
    PORT
      LAYER met3 ;
        RECT 251.480 165.960 252.080 166.560 ;
    END
  END FrameData_O[8]
  PIN FrameData_O[9]
    DIRECTION OUTPUT ;
    USE SIGNAL ;
    ANTENNADIFFAREA 0.702900 ;
    PORT
      LAYER met3 ;
        RECT 251.480 167.320 252.080 167.920 ;
    END
  END FrameData_O[9]
  PIN FrameStrobe[0]
    DIRECTION INPUT ;
    USE SIGNAL ;
    ANTENNAGATEAREA 5.247000 ;
    PORT
      LAYER met2 ;
        RECT 207.550 0.000 207.830 0.280 ;
    END
  END FrameStrobe[0]
  PIN FrameStrobe[10]
    DIRECTION INPUT ;
    USE SIGNAL ;
    ANTENNAGATEAREA 5.681700 ;
    ANTENNADIFFAREA 0.434700 ;
    PORT
      LAYER met2 ;
        RECT 225.950 0.000 226.230 0.280 ;
    END
  END FrameStrobe[10]
  PIN FrameStrobe[11]
    DIRECTION INPUT ;
    USE SIGNAL ;
    ANTENNAGATEAREA 5.247000 ;
    PORT
      LAYER met2 ;
        RECT 227.790 0.000 228.070 0.280 ;
    END
  END FrameStrobe[11]
  PIN FrameStrobe[12]
    DIRECTION INPUT ;
    USE SIGNAL ;
    ANTENNAGATEAREA 5.681700 ;
    ANTENNADIFFAREA 0.434700 ;
    PORT
      LAYER met2 ;
        RECT 229.630 0.000 229.910 0.280 ;
    END
  END FrameStrobe[12]
  PIN FrameStrobe[13]
    DIRECTION INPUT ;
    USE SIGNAL ;
    ANTENNAGATEAREA 3.095400 ;
    ANTENNADIFFAREA 0.869400 ;
    PORT
      LAYER met2 ;
        RECT 231.470 0.000 231.750 0.280 ;
    END
  END FrameStrobe[13]
  PIN FrameStrobe[14]
    DIRECTION INPUT ;
    USE SIGNAL ;
    ANTENNAGATEAREA 0.593700 ;
    ANTENNADIFFAREA 0.434700 ;
    PORT
      LAYER met2 ;
        RECT 233.310 0.000 233.590 0.280 ;
    END
  END FrameStrobe[14]
  PIN FrameStrobe[15]
    DIRECTION INPUT ;
    USE SIGNAL ;
    ANTENNAGATEAREA 0.593700 ;
    ANTENNADIFFAREA 0.434700 ;
    PORT
      LAYER met2 ;
        RECT 235.150 0.000 235.430 0.280 ;
    END
  END FrameStrobe[15]
  PIN FrameStrobe[16]
    DIRECTION INPUT ;
    USE SIGNAL ;
    ANTENNAGATEAREA 0.593700 ;
    ANTENNADIFFAREA 0.434700 ;
    PORT
      LAYER met2 ;
        RECT 236.990 0.000 237.270 0.280 ;
    END
  END FrameStrobe[16]
  PIN FrameStrobe[17]
    DIRECTION INPUT ;
    USE SIGNAL ;
    ANTENNAGATEAREA 0.593700 ;
    ANTENNADIFFAREA 0.434700 ;
    PORT
      LAYER met2 ;
        RECT 238.830 0.000 239.110 0.280 ;
    END
  END FrameStrobe[17]
  PIN FrameStrobe[18]
    DIRECTION INPUT ;
    USE SIGNAL ;
    ANTENNAGATEAREA 0.593700 ;
    ANTENNADIFFAREA 0.434700 ;
    PORT
      LAYER met2 ;
        RECT 240.670 0.000 240.950 0.280 ;
    END
  END FrameStrobe[18]
  PIN FrameStrobe[19]
    DIRECTION INPUT ;
    USE SIGNAL ;
    ANTENNAGATEAREA 0.159000 ;
    PORT
      LAYER met2 ;
        RECT 242.510 0.000 242.790 0.280 ;
    END
  END FrameStrobe[19]
  PIN FrameStrobe[1]
    DIRECTION INPUT ;
    USE SIGNAL ;
    ANTENNAGATEAREA 5.247000 ;
    PORT
      LAYER met2 ;
        RECT 209.390 0.000 209.670 0.280 ;
    END
  END FrameStrobe[1]
  PIN FrameStrobe[2]
    DIRECTION INPUT ;
    USE SIGNAL ;
    ANTENNAGATEAREA 6.985800 ;
    ANTENNADIFFAREA 1.738800 ;
    PORT
      LAYER met2 ;
        RECT 211.230 0.000 211.510 0.280 ;
    END
  END FrameStrobe[2]
  PIN FrameStrobe[3]
    DIRECTION INPUT ;
    USE SIGNAL ;
    ANTENNAGATEAREA 5.247000 ;
    PORT
      LAYER met2 ;
        RECT 213.070 0.000 213.350 0.280 ;
    END
  END FrameStrobe[3]
  PIN FrameStrobe[4]
    DIRECTION INPUT ;
    USE SIGNAL ;
    ANTENNAGATEAREA 7.420500 ;
    ANTENNADIFFAREA 2.173500 ;
    PORT
      LAYER met2 ;
        RECT 214.910 0.000 215.190 0.280 ;
    END
  END FrameStrobe[4]
  PIN FrameStrobe[5]
    DIRECTION INPUT ;
    USE SIGNAL ;
    ANTENNAGATEAREA 5.247000 ;
    PORT
      LAYER met2 ;
        RECT 216.750 0.000 217.030 0.280 ;
    END
  END FrameStrobe[5]
  PIN FrameStrobe[6]
    DIRECTION INPUT ;
    USE SIGNAL ;
    ANTENNAGATEAREA 5.247000 ;
    PORT
      LAYER met2 ;
        RECT 218.590 0.000 218.870 0.280 ;
    END
  END FrameStrobe[6]
  PIN FrameStrobe[7]
    DIRECTION INPUT ;
    USE SIGNAL ;
    ANTENNAGATEAREA 5.247000 ;
    PORT
      LAYER met2 ;
        RECT 220.430 0.000 220.710 0.280 ;
    END
  END FrameStrobe[7]
  PIN FrameStrobe[8]
    DIRECTION INPUT ;
    USE SIGNAL ;
    ANTENNAGATEAREA 5.247000 ;
    PORT
      LAYER met2 ;
        RECT 222.270 0.000 222.550 0.280 ;
    END
  END FrameStrobe[8]
  PIN FrameStrobe[9]
    DIRECTION INPUT ;
    USE SIGNAL ;
    ANTENNAGATEAREA 5.681700 ;
    ANTENNADIFFAREA 0.434700 ;
    PORT
      LAYER met2 ;
        RECT 224.110 0.000 224.390 0.280 ;
    END
  END FrameStrobe[9]
  PIN FrameStrobe_O[0]
    DIRECTION OUTPUT ;
    USE SIGNAL ;
    ANTENNADIFFAREA 0.702900 ;
    PORT
      LAYER met2 ;
        RECT 207.550 222.760 207.830 223.040 ;
    END
  END FrameStrobe_O[0]
  PIN FrameStrobe_O[10]
    DIRECTION OUTPUT ;
    USE SIGNAL ;
    ANTENNADIFFAREA 0.702900 ;
    PORT
      LAYER met2 ;
        RECT 225.950 222.760 226.230 223.040 ;
    END
  END FrameStrobe_O[10]
  PIN FrameStrobe_O[11]
    DIRECTION OUTPUT ;
    USE SIGNAL ;
    ANTENNADIFFAREA 0.702900 ;
    PORT
      LAYER met2 ;
        RECT 227.790 222.760 228.070 223.040 ;
    END
  END FrameStrobe_O[11]
  PIN FrameStrobe_O[12]
    DIRECTION OUTPUT ;
    USE SIGNAL ;
    ANTENNADIFFAREA 0.702900 ;
    PORT
      LAYER met2 ;
        RECT 229.630 222.760 229.910 223.040 ;
    END
  END FrameStrobe_O[12]
  PIN FrameStrobe_O[13]
    DIRECTION OUTPUT ;
    USE SIGNAL ;
    ANTENNADIFFAREA 0.702900 ;
    PORT
      LAYER met2 ;
        RECT 231.470 222.760 231.750 223.040 ;
    END
  END FrameStrobe_O[13]
  PIN FrameStrobe_O[14]
    DIRECTION OUTPUT ;
    USE SIGNAL ;
    ANTENNADIFFAREA 0.702900 ;
    PORT
      LAYER met2 ;
        RECT 233.310 222.760 233.590 223.040 ;
    END
  END FrameStrobe_O[14]
  PIN FrameStrobe_O[15]
    DIRECTION OUTPUT ;
    USE SIGNAL ;
    ANTENNADIFFAREA 0.702900 ;
    PORT
      LAYER met2 ;
        RECT 235.150 222.760 235.430 223.040 ;
    END
  END FrameStrobe_O[15]
  PIN FrameStrobe_O[16]
    DIRECTION OUTPUT ;
    USE SIGNAL ;
    ANTENNADIFFAREA 0.702900 ;
    PORT
      LAYER met2 ;
        RECT 236.990 222.760 237.270 223.040 ;
    END
  END FrameStrobe_O[16]
  PIN FrameStrobe_O[17]
    DIRECTION OUTPUT ;
    USE SIGNAL ;
    ANTENNADIFFAREA 0.702900 ;
    PORT
      LAYER met2 ;
        RECT 238.830 222.760 239.110 223.040 ;
    END
  END FrameStrobe_O[17]
  PIN FrameStrobe_O[18]
    DIRECTION OUTPUT ;
    USE SIGNAL ;
    ANTENNADIFFAREA 0.702900 ;
    PORT
      LAYER met2 ;
        RECT 240.670 222.760 240.950 223.040 ;
    END
  END FrameStrobe_O[18]
  PIN FrameStrobe_O[19]
    DIRECTION OUTPUT ;
    USE SIGNAL ;
    ANTENNADIFFAREA 0.702900 ;
    PORT
      LAYER met2 ;
        RECT 242.510 222.760 242.790 223.040 ;
    END
  END FrameStrobe_O[19]
  PIN FrameStrobe_O[1]
    DIRECTION OUTPUT ;
    USE SIGNAL ;
    ANTENNADIFFAREA 0.702900 ;
    PORT
      LAYER met2 ;
        RECT 209.390 222.760 209.670 223.040 ;
    END
  END FrameStrobe_O[1]
  PIN FrameStrobe_O[2]
    DIRECTION OUTPUT ;
    USE SIGNAL ;
    ANTENNADIFFAREA 0.702900 ;
    PORT
      LAYER met2 ;
        RECT 211.230 222.760 211.510 223.040 ;
    END
  END FrameStrobe_O[2]
  PIN FrameStrobe_O[3]
    DIRECTION OUTPUT ;
    USE SIGNAL ;
    ANTENNADIFFAREA 0.702900 ;
    PORT
      LAYER met2 ;
        RECT 213.070 222.760 213.350 223.040 ;
    END
  END FrameStrobe_O[3]
  PIN FrameStrobe_O[4]
    DIRECTION OUTPUT ;
    USE SIGNAL ;
    ANTENNADIFFAREA 0.702900 ;
    PORT
      LAYER met2 ;
        RECT 214.910 222.760 215.190 223.040 ;
    END
  END FrameStrobe_O[4]
  PIN FrameStrobe_O[5]
    DIRECTION OUTPUT ;
    USE SIGNAL ;
    ANTENNADIFFAREA 0.702900 ;
    PORT
      LAYER met2 ;
        RECT 216.750 222.760 217.030 223.040 ;
    END
  END FrameStrobe_O[5]
  PIN FrameStrobe_O[6]
    DIRECTION OUTPUT ;
    USE SIGNAL ;
    ANTENNADIFFAREA 0.702900 ;
    PORT
      LAYER met2 ;
        RECT 218.590 222.760 218.870 223.040 ;
    END
  END FrameStrobe_O[6]
  PIN FrameStrobe_O[7]
    DIRECTION OUTPUT ;
    USE SIGNAL ;
    ANTENNADIFFAREA 0.702900 ;
    PORT
      LAYER met2 ;
        RECT 220.430 222.760 220.710 223.040 ;
    END
  END FrameStrobe_O[7]
  PIN FrameStrobe_O[8]
    DIRECTION OUTPUT ;
    USE SIGNAL ;
    ANTENNADIFFAREA 0.702900 ;
    PORT
      LAYER met2 ;
        RECT 222.270 222.760 222.550 223.040 ;
    END
  END FrameStrobe_O[8]
  PIN FrameStrobe_O[9]
    DIRECTION OUTPUT ;
    USE SIGNAL ;
    ANTENNADIFFAREA 0.702900 ;
    PORT
      LAYER met2 ;
        RECT 224.110 222.760 224.390 223.040 ;
    END
  END FrameStrobe_O[9]
  PIN N1BEG[0]
    DIRECTION OUTPUT ;
    USE SIGNAL ;
    ANTENNADIFFAREA 0.702900 ;
    PORT
      LAYER met2 ;
        RECT 16.190 222.760 16.470 223.040 ;
    END
  END N1BEG[0]
  PIN N1BEG[1]
    DIRECTION OUTPUT ;
    USE SIGNAL ;
    ANTENNADIFFAREA 0.702900 ;
    PORT
      LAYER met2 ;
        RECT 18.030 222.760 18.310 223.040 ;
    END
  END N1BEG[1]
  PIN N1BEG[2]
    DIRECTION OUTPUT ;
    USE SIGNAL ;
    ANTENNADIFFAREA 0.702900 ;
    PORT
      LAYER met2 ;
        RECT 19.870 222.760 20.150 223.040 ;
    END
  END N1BEG[2]
  PIN N1BEG[3]
    DIRECTION OUTPUT ;
    USE SIGNAL ;
    ANTENNADIFFAREA 0.702900 ;
    PORT
      LAYER met2 ;
        RECT 21.710 222.760 21.990 223.040 ;
    END
  END N1BEG[3]
  PIN N1END[0]
    DIRECTION INPUT ;
    USE SIGNAL ;
    ANTENNAGATEAREA 1.958700 ;
    ANTENNADIFFAREA 0.434700 ;
    PORT
      LAYER met2 ;
        RECT 16.190 0.000 16.470 0.280 ;
    END
  END N1END[0]
  PIN N1END[1]
    DIRECTION INPUT ;
    USE SIGNAL ;
    ANTENNAGATEAREA 1.590000 ;
    PORT
      LAYER met2 ;
        RECT 18.030 0.000 18.310 0.280 ;
    END
  END N1END[1]
  PIN N1END[2]
    DIRECTION INPUT ;
    USE SIGNAL ;
    ANTENNAGATEAREA 2.459400 ;
    ANTENNADIFFAREA 0.869400 ;
    PORT
      LAYER met2 ;
        RECT 19.870 0.000 20.150 0.280 ;
    END
  END N1END[2]
  PIN N1END[3]
    DIRECTION INPUT ;
    USE SIGNAL ;
    ANTENNAGATEAREA 1.590000 ;
    PORT
      LAYER met2 ;
        RECT 21.710 0.000 21.990 0.280 ;
    END
  END N1END[3]
  PIN N2BEG[0]
    DIRECTION OUTPUT ;
    USE SIGNAL ;
    ANTENNADIFFAREA 0.702900 ;
    PORT
      LAYER met2 ;
        RECT 23.550 222.760 23.830 223.040 ;
    END
  END N2BEG[0]
  PIN N2BEG[1]
    DIRECTION OUTPUT ;
    USE SIGNAL ;
    ANTENNADIFFAREA 0.702900 ;
    PORT
      LAYER met2 ;
        RECT 25.390 222.760 25.670 223.040 ;
    END
  END N2BEG[1]
  PIN N2BEG[2]
    DIRECTION OUTPUT ;
    USE SIGNAL ;
    ANTENNADIFFAREA 0.702900 ;
    PORT
      LAYER met2 ;
        RECT 27.230 222.760 27.510 223.040 ;
    END
  END N2BEG[2]
  PIN N2BEG[3]
    DIRECTION OUTPUT ;
    USE SIGNAL ;
    ANTENNADIFFAREA 0.702900 ;
    PORT
      LAYER met2 ;
        RECT 29.070 222.760 29.350 223.040 ;
    END
  END N2BEG[3]
  PIN N2BEG[4]
    DIRECTION OUTPUT ;
    USE SIGNAL ;
    ANTENNADIFFAREA 0.702900 ;
    PORT
      LAYER met2 ;
        RECT 30.910 222.760 31.190 223.040 ;
    END
  END N2BEG[4]
  PIN N2BEG[5]
    DIRECTION OUTPUT ;
    USE SIGNAL ;
    ANTENNADIFFAREA 0.702900 ;
    PORT
      LAYER met2 ;
        RECT 32.750 222.760 33.030 223.040 ;
    END
  END N2BEG[5]
  PIN N2BEG[6]
    DIRECTION OUTPUT ;
    USE SIGNAL ;
    ANTENNADIFFAREA 0.702900 ;
    PORT
      LAYER met2 ;
        RECT 34.590 222.760 34.870 223.040 ;
    END
  END N2BEG[6]
  PIN N2BEG[7]
    DIRECTION OUTPUT ;
    USE SIGNAL ;
    ANTENNADIFFAREA 0.702900 ;
    PORT
      LAYER met2 ;
        RECT 36.430 222.760 36.710 223.040 ;
    END
  END N2BEG[7]
  PIN N2BEGb[0]
    DIRECTION OUTPUT ;
    USE SIGNAL ;
    ANTENNADIFFAREA 0.702900 ;
    PORT
      LAYER met2 ;
        RECT 38.270 222.760 38.550 223.040 ;
    END
  END N2BEGb[0]
  PIN N2BEGb[1]
    DIRECTION OUTPUT ;
    USE SIGNAL ;
    ANTENNADIFFAREA 0.702900 ;
    PORT
      LAYER met2 ;
        RECT 40.110 222.760 40.390 223.040 ;
    END
  END N2BEGb[1]
  PIN N2BEGb[2]
    DIRECTION OUTPUT ;
    USE SIGNAL ;
    ANTENNADIFFAREA 0.702900 ;
    PORT
      LAYER met2 ;
        RECT 41.950 222.760 42.230 223.040 ;
    END
  END N2BEGb[2]
  PIN N2BEGb[3]
    DIRECTION OUTPUT ;
    USE SIGNAL ;
    ANTENNADIFFAREA 0.702900 ;
    PORT
      LAYER met2 ;
        RECT 43.790 222.760 44.070 223.040 ;
    END
  END N2BEGb[3]
  PIN N2BEGb[4]
    DIRECTION OUTPUT ;
    USE SIGNAL ;
    ANTENNADIFFAREA 0.702900 ;
    PORT
      LAYER met2 ;
        RECT 45.630 222.760 45.910 223.040 ;
    END
  END N2BEGb[4]
  PIN N2BEGb[5]
    DIRECTION OUTPUT ;
    USE SIGNAL ;
    ANTENNADIFFAREA 0.702900 ;
    PORT
      LAYER met2 ;
        RECT 47.470 222.760 47.750 223.040 ;
    END
  END N2BEGb[5]
  PIN N2BEGb[6]
    DIRECTION OUTPUT ;
    USE SIGNAL ;
    ANTENNADIFFAREA 0.702900 ;
    PORT
      LAYER met2 ;
        RECT 49.310 222.760 49.590 223.040 ;
    END
  END N2BEGb[6]
  PIN N2BEGb[7]
    DIRECTION OUTPUT ;
    USE SIGNAL ;
    ANTENNADIFFAREA 0.702900 ;
    PORT
      LAYER met2 ;
        RECT 51.150 222.760 51.430 223.040 ;
    END
  END N2BEGb[7]
  PIN N2END[0]
    DIRECTION INPUT ;
    USE SIGNAL ;
    ANTENNAGATEAREA 1.239000 ;
    PORT
      LAYER met2 ;
        RECT 38.270 0.000 38.550 0.280 ;
    END
  END N2END[0]
  PIN N2END[1]
    DIRECTION INPUT ;
    USE SIGNAL ;
    ANTENNAGATEAREA 1.449000 ;
    PORT
      LAYER met2 ;
        RECT 40.110 0.000 40.390 0.280 ;
    END
  END N2END[1]
  PIN N2END[2]
    DIRECTION INPUT ;
    USE SIGNAL ;
    ANTENNAGATEAREA 1.113000 ;
    PORT
      LAYER met2 ;
        RECT 41.950 0.000 42.230 0.280 ;
    END
  END N2END[2]
  PIN N2END[3]
    DIRECTION INPUT ;
    USE SIGNAL ;
    ANTENNAGATEAREA 1.491000 ;
    PORT
      LAYER met2 ;
        RECT 43.790 0.000 44.070 0.280 ;
    END
  END N2END[3]
  PIN N2END[4]
    DIRECTION INPUT ;
    USE SIGNAL ;
    ANTENNAGATEAREA 0.954000 ;
    PORT
      LAYER met2 ;
        RECT 45.630 0.000 45.910 0.280 ;
    END
  END N2END[4]
  PIN N2END[5]
    DIRECTION INPUT ;
    USE SIGNAL ;
    ANTENNAGATEAREA 2.968500 ;
    ANTENNADIFFAREA 2.173500 ;
    PORT
      LAYER met2 ;
        RECT 47.470 0.000 47.750 0.280 ;
    END
  END N2END[5]
  PIN N2END[6]
    DIRECTION INPUT ;
    USE SIGNAL ;
    ANTENNAGATEAREA 0.795000 ;
    PORT
      LAYER met2 ;
        RECT 49.310 0.000 49.590 0.280 ;
    END
  END N2END[6]
  PIN N2END[7]
    DIRECTION INPUT ;
    USE SIGNAL ;
    ANTENNAGATEAREA 3.562200 ;
    ANTENNADIFFAREA 2.608200 ;
    PORT
      LAYER met2 ;
        RECT 51.150 0.000 51.430 0.280 ;
    END
  END N2END[7]
  PIN N2MID[0]
    DIRECTION INPUT ;
    USE SIGNAL ;
    ANTENNAGATEAREA 0.603000 ;
    PORT
      LAYER met2 ;
        RECT 23.550 0.000 23.830 0.280 ;
    END
  END N2MID[0]
  PIN N2MID[1]
    DIRECTION INPUT ;
    USE SIGNAL ;
    ANTENNAGATEAREA 0.696000 ;
    PORT
      LAYER met2 ;
        RECT 25.390 0.000 25.670 0.280 ;
    END
  END N2MID[1]
  PIN N2MID[2]
    DIRECTION INPUT ;
    USE SIGNAL ;
    ANTENNAGATEAREA 1.560900 ;
    ANTENNADIFFAREA 0.869400 ;
    PORT
      LAYER met2 ;
        RECT 27.230 0.000 27.510 0.280 ;
    END
  END N2MID[2]
  PIN N2MID[3]
    DIRECTION INPUT ;
    USE SIGNAL ;
    ANTENNAGATEAREA 2.968500 ;
    ANTENNADIFFAREA 2.173500 ;
    PORT
      LAYER met2 ;
        RECT 29.070 0.000 29.350 0.280 ;
    END
  END N2MID[3]
  PIN N2MID[4]
    DIRECTION INPUT ;
    USE SIGNAL ;
    ANTENNAGATEAREA 0.972000 ;
    PORT
      LAYER met2 ;
        RECT 30.910 0.000 31.190 0.280 ;
    END
  END N2MID[4]
  PIN N2MID[5]
    DIRECTION INPUT ;
    USE SIGNAL ;
    ANTENNAGATEAREA 1.229700 ;
    ANTENNADIFFAREA 0.434700 ;
    PORT
      LAYER met2 ;
        RECT 32.750 0.000 33.030 0.280 ;
    END
  END N2MID[5]
  PIN N2MID[6]
    DIRECTION INPUT ;
    USE SIGNAL ;
    ANTENNAGATEAREA 0.603000 ;
    PORT
      LAYER met2 ;
        RECT 34.590 0.000 34.870 0.280 ;
    END
  END N2MID[6]
  PIN N2MID[7]
    DIRECTION INPUT ;
    USE SIGNAL ;
    ANTENNAGATEAREA 1.130700 ;
    ANTENNADIFFAREA 0.434700 ;
    PORT
      LAYER met2 ;
        RECT 36.430 0.000 36.710 0.280 ;
    END
  END N2MID[7]
  PIN N4BEG[0]
    DIRECTION OUTPUT ;
    USE SIGNAL ;
    ANTENNADIFFAREA 0.702900 ;
    PORT
      LAYER met2 ;
        RECT 52.990 222.760 53.270 223.040 ;
    END
  END N4BEG[0]
  PIN N4BEG[10]
    DIRECTION OUTPUT ;
    USE SIGNAL ;
    ANTENNADIFFAREA 0.702900 ;
    PORT
      LAYER met2 ;
        RECT 71.390 222.760 71.670 223.040 ;
    END
  END N4BEG[10]
  PIN N4BEG[11]
    DIRECTION OUTPUT ;
    USE SIGNAL ;
    ANTENNADIFFAREA 0.702900 ;
    PORT
      LAYER met2 ;
        RECT 73.230 222.760 73.510 223.040 ;
    END
  END N4BEG[11]
  PIN N4BEG[12]
    DIRECTION OUTPUT ;
    USE SIGNAL ;
    ANTENNADIFFAREA 0.702900 ;
    PORT
      LAYER met2 ;
        RECT 75.070 222.760 75.350 223.040 ;
    END
  END N4BEG[12]
  PIN N4BEG[13]
    DIRECTION OUTPUT ;
    USE SIGNAL ;
    ANTENNADIFFAREA 0.702900 ;
    PORT
      LAYER met2 ;
        RECT 76.910 222.760 77.190 223.040 ;
    END
  END N4BEG[13]
  PIN N4BEG[14]
    DIRECTION OUTPUT ;
    USE SIGNAL ;
    ANTENNADIFFAREA 0.702900 ;
    PORT
      LAYER met2 ;
        RECT 78.750 222.760 79.030 223.040 ;
    END
  END N4BEG[14]
  PIN N4BEG[15]
    DIRECTION OUTPUT ;
    USE SIGNAL ;
    ANTENNADIFFAREA 0.702900 ;
    PORT
      LAYER met2 ;
        RECT 80.590 222.760 80.870 223.040 ;
    END
  END N4BEG[15]
  PIN N4BEG[1]
    DIRECTION OUTPUT ;
    USE SIGNAL ;
    ANTENNADIFFAREA 0.702900 ;
    PORT
      LAYER met2 ;
        RECT 54.830 222.760 55.110 223.040 ;
    END
  END N4BEG[1]
  PIN N4BEG[2]
    DIRECTION OUTPUT ;
    USE SIGNAL ;
    ANTENNADIFFAREA 0.702900 ;
    PORT
      LAYER met2 ;
        RECT 56.670 222.760 56.950 223.040 ;
    END
  END N4BEG[2]
  PIN N4BEG[3]
    DIRECTION OUTPUT ;
    USE SIGNAL ;
    ANTENNADIFFAREA 0.702900 ;
    PORT
      LAYER met2 ;
        RECT 58.510 222.760 58.790 223.040 ;
    END
  END N4BEG[3]
  PIN N4BEG[4]
    DIRECTION OUTPUT ;
    USE SIGNAL ;
    ANTENNADIFFAREA 0.702900 ;
    PORT
      LAYER met2 ;
        RECT 60.350 222.760 60.630 223.040 ;
    END
  END N4BEG[4]
  PIN N4BEG[5]
    DIRECTION OUTPUT ;
    USE SIGNAL ;
    ANTENNADIFFAREA 0.702900 ;
    PORT
      LAYER met2 ;
        RECT 62.190 222.760 62.470 223.040 ;
    END
  END N4BEG[5]
  PIN N4BEG[6]
    DIRECTION OUTPUT ;
    USE SIGNAL ;
    ANTENNADIFFAREA 0.702900 ;
    PORT
      LAYER met2 ;
        RECT 64.030 222.760 64.310 223.040 ;
    END
  END N4BEG[6]
  PIN N4BEG[7]
    DIRECTION OUTPUT ;
    USE SIGNAL ;
    ANTENNADIFFAREA 0.702900 ;
    PORT
      LAYER met2 ;
        RECT 65.870 222.760 66.150 223.040 ;
    END
  END N4BEG[7]
  PIN N4BEG[8]
    DIRECTION OUTPUT ;
    USE SIGNAL ;
    ANTENNADIFFAREA 0.702900 ;
    PORT
      LAYER met2 ;
        RECT 67.710 222.760 67.990 223.040 ;
    END
  END N4BEG[8]
  PIN N4BEG[9]
    DIRECTION OUTPUT ;
    USE SIGNAL ;
    ANTENNADIFFAREA 0.702900 ;
    PORT
      LAYER met2 ;
        RECT 69.550 222.760 69.830 223.040 ;
    END
  END N4BEG[9]
  PIN N4END[0]
    DIRECTION INPUT ;
    USE SIGNAL ;
    ANTENNAGATEAREA 1.098000 ;
    PORT
      LAYER met2 ;
        RECT 52.990 0.000 53.270 0.280 ;
    END
  END N4END[0]
  PIN N4END[10]
    DIRECTION INPUT ;
    USE SIGNAL ;
    ANTENNAGATEAREA 0.159000 ;
    PORT
      LAYER met2 ;
        RECT 71.390 0.000 71.670 0.280 ;
    END
  END N4END[10]
  PIN N4END[11]
    DIRECTION INPUT ;
    USE SIGNAL ;
    ANTENNAGATEAREA 0.159000 ;
    PORT
      LAYER met2 ;
        RECT 73.230 0.000 73.510 0.280 ;
    END
  END N4END[11]
  PIN N4END[12]
    DIRECTION INPUT ;
    USE SIGNAL ;
    ANTENNAGATEAREA 0.159000 ;
    PORT
      LAYER met2 ;
        RECT 75.070 0.000 75.350 0.280 ;
    END
  END N4END[12]
  PIN N4END[13]
    DIRECTION INPUT ;
    USE SIGNAL ;
    ANTENNAGATEAREA 0.159000 ;
    PORT
      LAYER met2 ;
        RECT 76.910 0.000 77.190 0.280 ;
    END
  END N4END[13]
  PIN N4END[14]
    DIRECTION INPUT ;
    USE SIGNAL ;
    ANTENNAGATEAREA 0.159000 ;
    PORT
      LAYER met2 ;
        RECT 78.750 0.000 79.030 0.280 ;
    END
  END N4END[14]
  PIN N4END[15]
    DIRECTION INPUT ;
    USE SIGNAL ;
    ANTENNAGATEAREA 0.159000 ;
    PORT
      LAYER met2 ;
        RECT 80.590 0.000 80.870 0.280 ;
    END
  END N4END[15]
  PIN N4END[1]
    DIRECTION INPUT ;
    USE SIGNAL ;
    ANTENNAGATEAREA 0.795000 ;
    PORT
      LAYER met2 ;
        RECT 54.830 0.000 55.110 0.280 ;
    END
  END N4END[1]
  PIN N4END[2]
    DIRECTION INPUT ;
    USE SIGNAL ;
    ANTENNAGATEAREA 1.196700 ;
    ANTENNADIFFAREA 0.434700 ;
    PORT
      LAYER met2 ;
        RECT 56.670 0.000 56.950 0.280 ;
    END
  END N4END[2]
  PIN N4END[3]
    DIRECTION INPUT ;
    USE SIGNAL ;
    ANTENNAGATEAREA 1.664400 ;
    ANTENNADIFFAREA 0.869400 ;
    PORT
      LAYER met2 ;
        RECT 58.510 0.000 58.790 0.280 ;
    END
  END N4END[3]
  PIN N4END[4]
    DIRECTION INPUT ;
    USE SIGNAL ;
    ANTENNAGATEAREA 0.159000 ;
    PORT
      LAYER met2 ;
        RECT 60.350 0.000 60.630 0.280 ;
    END
  END N4END[4]
  PIN N4END[5]
    DIRECTION INPUT ;
    USE SIGNAL ;
    ANTENNAGATEAREA 0.159000 ;
    PORT
      LAYER met2 ;
        RECT 62.190 0.000 62.470 0.280 ;
    END
  END N4END[5]
  PIN N4END[6]
    DIRECTION INPUT ;
    USE SIGNAL ;
    ANTENNAGATEAREA 0.159000 ;
    PORT
      LAYER met2 ;
        RECT 64.030 0.000 64.310 0.280 ;
    END
  END N4END[6]
  PIN N4END[7]
    DIRECTION INPUT ;
    USE SIGNAL ;
    ANTENNAGATEAREA 0.159000 ;
    PORT
      LAYER met2 ;
        RECT 65.870 0.000 66.150 0.280 ;
    END
  END N4END[7]
  PIN N4END[8]
    DIRECTION INPUT ;
    USE SIGNAL ;
    ANTENNAGATEAREA 0.159000 ;
    PORT
      LAYER met2 ;
        RECT 67.710 0.000 67.990 0.280 ;
    END
  END N4END[8]
  PIN N4END[9]
    DIRECTION INPUT ;
    USE SIGNAL ;
    ANTENNAGATEAREA 0.159000 ;
    PORT
      LAYER met2 ;
        RECT 69.550 0.000 69.830 0.280 ;
    END
  END N4END[9]
  PIN NN4BEG[0]
    DIRECTION OUTPUT ;
    USE SIGNAL ;
    ANTENNADIFFAREA 0.702900 ;
    PORT
      LAYER met2 ;
        RECT 82.430 222.760 82.710 223.040 ;
    END
  END NN4BEG[0]
  PIN NN4BEG[10]
    DIRECTION OUTPUT ;
    USE SIGNAL ;
    ANTENNADIFFAREA 0.702900 ;
    PORT
      LAYER met2 ;
        RECT 100.830 222.760 101.110 223.040 ;
    END
  END NN4BEG[10]
  PIN NN4BEG[11]
    DIRECTION OUTPUT ;
    USE SIGNAL ;
    ANTENNADIFFAREA 0.702900 ;
    PORT
      LAYER met2 ;
        RECT 102.670 222.760 102.950 223.040 ;
    END
  END NN4BEG[11]
  PIN NN4BEG[12]
    DIRECTION OUTPUT ;
    USE SIGNAL ;
    ANTENNADIFFAREA 0.702900 ;
    PORT
      LAYER met2 ;
        RECT 104.510 222.760 104.790 223.040 ;
    END
  END NN4BEG[12]
  PIN NN4BEG[13]
    DIRECTION OUTPUT ;
    USE SIGNAL ;
    ANTENNADIFFAREA 0.702900 ;
    PORT
      LAYER met2 ;
        RECT 106.350 222.760 106.630 223.040 ;
    END
  END NN4BEG[13]
  PIN NN4BEG[14]
    DIRECTION OUTPUT ;
    USE SIGNAL ;
    ANTENNADIFFAREA 0.702900 ;
    PORT
      LAYER met2 ;
        RECT 108.190 222.760 108.470 223.040 ;
    END
  END NN4BEG[14]
  PIN NN4BEG[15]
    DIRECTION OUTPUT ;
    USE SIGNAL ;
    ANTENNADIFFAREA 0.702900 ;
    PORT
      LAYER met2 ;
        RECT 110.030 222.760 110.310 223.040 ;
    END
  END NN4BEG[15]
  PIN NN4BEG[1]
    DIRECTION OUTPUT ;
    USE SIGNAL ;
    ANTENNADIFFAREA 0.702900 ;
    PORT
      LAYER met2 ;
        RECT 84.270 222.760 84.550 223.040 ;
    END
  END NN4BEG[1]
  PIN NN4BEG[2]
    DIRECTION OUTPUT ;
    USE SIGNAL ;
    ANTENNADIFFAREA 0.702900 ;
    PORT
      LAYER met2 ;
        RECT 86.110 222.760 86.390 223.040 ;
    END
  END NN4BEG[2]
  PIN NN4BEG[3]
    DIRECTION OUTPUT ;
    USE SIGNAL ;
    ANTENNADIFFAREA 0.702900 ;
    PORT
      LAYER met2 ;
        RECT 87.950 222.760 88.230 223.040 ;
    END
  END NN4BEG[3]
  PIN NN4BEG[4]
    DIRECTION OUTPUT ;
    USE SIGNAL ;
    ANTENNADIFFAREA 0.702900 ;
    PORT
      LAYER met2 ;
        RECT 89.790 222.760 90.070 223.040 ;
    END
  END NN4BEG[4]
  PIN NN4BEG[5]
    DIRECTION OUTPUT ;
    USE SIGNAL ;
    ANTENNADIFFAREA 0.702900 ;
    PORT
      LAYER met2 ;
        RECT 91.630 222.760 91.910 223.040 ;
    END
  END NN4BEG[5]
  PIN NN4BEG[6]
    DIRECTION OUTPUT ;
    USE SIGNAL ;
    ANTENNADIFFAREA 0.702900 ;
    PORT
      LAYER met2 ;
        RECT 93.470 222.760 93.750 223.040 ;
    END
  END NN4BEG[6]
  PIN NN4BEG[7]
    DIRECTION OUTPUT ;
    USE SIGNAL ;
    ANTENNADIFFAREA 0.702900 ;
    PORT
      LAYER met2 ;
        RECT 95.310 222.760 95.590 223.040 ;
    END
  END NN4BEG[7]
  PIN NN4BEG[8]
    DIRECTION OUTPUT ;
    USE SIGNAL ;
    ANTENNADIFFAREA 0.702900 ;
    PORT
      LAYER met2 ;
        RECT 97.150 222.760 97.430 223.040 ;
    END
  END NN4BEG[8]
  PIN NN4BEG[9]
    DIRECTION OUTPUT ;
    USE SIGNAL ;
    ANTENNADIFFAREA 0.702900 ;
    PORT
      LAYER met2 ;
        RECT 98.990 222.760 99.270 223.040 ;
    END
  END NN4BEG[9]
  PIN NN4END[0]
    DIRECTION INPUT ;
    USE SIGNAL ;
    ANTENNAGATEAREA 2.968500 ;
    ANTENNADIFFAREA 2.173500 ;
    PORT
      LAYER met2 ;
        RECT 82.430 0.000 82.710 0.280 ;
    END
  END NN4END[0]
  PIN NN4END[10]
    DIRECTION INPUT ;
    USE SIGNAL ;
    ANTENNAGATEAREA 0.159000 ;
    PORT
      LAYER met2 ;
        RECT 100.830 0.000 101.110 0.280 ;
    END
  END NN4END[10]
  PIN NN4END[11]
    DIRECTION INPUT ;
    USE SIGNAL ;
    ANTENNAGATEAREA 0.159000 ;
    PORT
      LAYER met2 ;
        RECT 102.670 0.000 102.950 0.280 ;
    END
  END NN4END[11]
  PIN NN4END[12]
    DIRECTION INPUT ;
    USE SIGNAL ;
    ANTENNAGATEAREA 0.159000 ;
    PORT
      LAYER met2 ;
        RECT 104.510 0.000 104.790 0.280 ;
    END
  END NN4END[12]
  PIN NN4END[13]
    DIRECTION INPUT ;
    USE SIGNAL ;
    ANTENNAGATEAREA 0.159000 ;
    PORT
      LAYER met2 ;
        RECT 106.350 0.000 106.630 0.280 ;
    END
  END NN4END[13]
  PIN NN4END[14]
    DIRECTION INPUT ;
    USE SIGNAL ;
    ANTENNAGATEAREA 0.159000 ;
    PORT
      LAYER met2 ;
        RECT 108.190 0.000 108.470 0.280 ;
    END
  END NN4END[14]
  PIN NN4END[15]
    DIRECTION INPUT ;
    USE SIGNAL ;
    ANTENNAGATEAREA 0.159000 ;
    PORT
      LAYER met2 ;
        RECT 110.030 0.000 110.310 0.280 ;
    END
  END NN4END[15]
  PIN NN4END[1]
    DIRECTION INPUT ;
    USE SIGNAL ;
    ANTENNAGATEAREA 1.229700 ;
    ANTENNADIFFAREA 0.434700 ;
    PORT
      LAYER met2 ;
        RECT 84.270 0.000 84.550 0.280 ;
    END
  END NN4END[1]
  PIN NN4END[2]
    DIRECTION INPUT ;
    USE SIGNAL ;
    ANTENNAGATEAREA 1.285200 ;
    ANTENNADIFFAREA 0.434700 ;
    PORT
      LAYER met2 ;
        RECT 86.110 0.000 86.390 0.280 ;
    END
  END NN4END[2]
  PIN NN4END[3]
    DIRECTION INPUT ;
    USE SIGNAL ;
    ANTENNAGATEAREA 1.318200 ;
    ANTENNADIFFAREA 0.434700 ;
    PORT
      LAYER met2 ;
        RECT 87.950 0.000 88.230 0.280 ;
    END
  END NN4END[3]
  PIN NN4END[4]
    DIRECTION INPUT ;
    USE SIGNAL ;
    ANTENNAGATEAREA 0.159000 ;
    PORT
      LAYER met2 ;
        RECT 89.790 0.000 90.070 0.280 ;
    END
  END NN4END[4]
  PIN NN4END[5]
    DIRECTION INPUT ;
    USE SIGNAL ;
    ANTENNAGATEAREA 0.159000 ;
    PORT
      LAYER met2 ;
        RECT 91.630 0.000 91.910 0.280 ;
    END
  END NN4END[5]
  PIN NN4END[6]
    DIRECTION INPUT ;
    USE SIGNAL ;
    ANTENNAGATEAREA 0.159000 ;
    PORT
      LAYER met2 ;
        RECT 93.470 0.000 93.750 0.280 ;
    END
  END NN4END[6]
  PIN NN4END[7]
    DIRECTION INPUT ;
    USE SIGNAL ;
    ANTENNAGATEAREA 0.159000 ;
    PORT
      LAYER met2 ;
        RECT 95.310 0.000 95.590 0.280 ;
    END
  END NN4END[7]
  PIN NN4END[8]
    DIRECTION INPUT ;
    USE SIGNAL ;
    ANTENNAGATEAREA 0.159000 ;
    PORT
      LAYER met2 ;
        RECT 97.150 0.000 97.430 0.280 ;
    END
  END NN4END[8]
  PIN NN4END[9]
    DIRECTION INPUT ;
    USE SIGNAL ;
    ANTENNAGATEAREA 0.159000 ;
    PORT
      LAYER met2 ;
        RECT 98.990 0.000 99.270 0.280 ;
    END
  END NN4END[9]
  PIN N_GBUF_BEG[0]
    DIRECTION OUTPUT ;
    USE SIGNAL ;
    ANTENNADIFFAREA 0.702900 ;
    PORT
      LAYER met2 ;
        RECT 8.830 222.760 9.110 223.040 ;
    END
  END N_GBUF_BEG[0]
  PIN N_GBUF_BEG[1]
    DIRECTION OUTPUT ;
    USE SIGNAL ;
    ANTENNADIFFAREA 0.702900 ;
    PORT
      LAYER met2 ;
        RECT 10.670 222.760 10.950 223.040 ;
    END
  END N_GBUF_BEG[1]
  PIN N_GBUF_BEG[2]
    DIRECTION OUTPUT ;
    USE SIGNAL ;
    ANTENNADIFFAREA 0.702900 ;
    PORT
      LAYER met2 ;
        RECT 12.510 222.760 12.790 223.040 ;
    END
  END N_GBUF_BEG[2]
  PIN N_GBUF_BEG[3]
    DIRECTION OUTPUT ;
    USE SIGNAL ;
    ANTENNADIFFAREA 0.702900 ;
    PORT
      LAYER met2 ;
        RECT 14.350 222.760 14.630 223.040 ;
    END
  END N_GBUF_BEG[3]
  PIN N_GBUF_END[0]
    DIRECTION INPUT ;
    USE SIGNAL ;
    ANTENNAGATEAREA 0.852000 ;
    PORT
      LAYER met2 ;
        RECT 8.830 0.000 9.110 0.280 ;
    END
  END N_GBUF_END[0]
  PIN N_GBUF_END[1]
    DIRECTION INPUT ;
    USE SIGNAL ;
    ANTENNAGATEAREA 0.636000 ;
    PORT
      LAYER met2 ;
        RECT 10.670 0.000 10.950 0.280 ;
    END
  END N_GBUF_END[1]
  PIN N_GBUF_END[2]
    DIRECTION INPUT ;
    USE SIGNAL ;
    ANTENNAGATEAREA 0.636000 ;
    PORT
      LAYER met2 ;
        RECT 12.510 0.000 12.790 0.280 ;
    END
  END N_GBUF_END[2]
  PIN N_GBUF_END[3]
    DIRECTION INPUT ;
    USE SIGNAL ;
    ANTENNAGATEAREA 0.636000 ;
    PORT
      LAYER met2 ;
        RECT 14.350 0.000 14.630 0.280 ;
    END
  END N_GBUF_END[3]
  PIN S1BEG[0]
    DIRECTION OUTPUT ;
    USE SIGNAL ;
    ANTENNADIFFAREA 0.702900 ;
    PORT
      LAYER met2 ;
        RECT 111.870 0.000 112.150 0.280 ;
    END
  END S1BEG[0]
  PIN S1BEG[1]
    DIRECTION OUTPUT ;
    USE SIGNAL ;
    ANTENNADIFFAREA 0.702900 ;
    PORT
      LAYER met2 ;
        RECT 113.710 0.000 113.990 0.280 ;
    END
  END S1BEG[1]
  PIN S1BEG[2]
    DIRECTION OUTPUT ;
    USE SIGNAL ;
    ANTENNADIFFAREA 0.702900 ;
    PORT
      LAYER met2 ;
        RECT 115.550 0.000 115.830 0.280 ;
    END
  END S1BEG[2]
  PIN S1BEG[3]
    DIRECTION OUTPUT ;
    USE SIGNAL ;
    ANTENNADIFFAREA 0.702900 ;
    PORT
      LAYER met2 ;
        RECT 117.390 0.000 117.670 0.280 ;
    END
  END S1BEG[3]
  PIN S1END[0]
    DIRECTION INPUT ;
    USE SIGNAL ;
    ANTENNAGATEAREA 1.239000 ;
    PORT
      LAYER met2 ;
        RECT 111.870 222.760 112.150 223.040 ;
    END
  END S1END[0]
  PIN S1END[1]
    DIRECTION INPUT ;
    USE SIGNAL ;
    ANTENNAGATEAREA 2.576100 ;
    ANTENNADIFFAREA 1.304100 ;
    PORT
      LAYER met2 ;
        RECT 113.710 222.760 113.990 223.040 ;
    END
  END S1END[1]
  PIN S1END[2]
    DIRECTION INPUT ;
    USE SIGNAL ;
    ANTENNAGATEAREA 1.706700 ;
    ANTENNADIFFAREA 0.434700 ;
    PORT
      LAYER met2 ;
        RECT 115.550 222.760 115.830 223.040 ;
    END
  END S1END[2]
  PIN S1END[3]
    DIRECTION INPUT ;
    USE SIGNAL ;
    ANTENNAGATEAREA 1.272000 ;
    PORT
      LAYER met2 ;
        RECT 117.390 222.760 117.670 223.040 ;
    END
  END S1END[3]
  PIN S2BEG[0]
    DIRECTION OUTPUT ;
    USE SIGNAL ;
    ANTENNADIFFAREA 0.702900 ;
    PORT
      LAYER met2 ;
        RECT 119.230 0.000 119.510 0.280 ;
    END
  END S2BEG[0]
  PIN S2BEG[1]
    DIRECTION OUTPUT ;
    USE SIGNAL ;
    ANTENNADIFFAREA 0.702900 ;
    PORT
      LAYER met2 ;
        RECT 121.070 0.000 121.350 0.280 ;
    END
  END S2BEG[1]
  PIN S2BEG[2]
    DIRECTION OUTPUT ;
    USE SIGNAL ;
    ANTENNADIFFAREA 0.702900 ;
    PORT
      LAYER met2 ;
        RECT 122.910 0.000 123.190 0.280 ;
    END
  END S2BEG[2]
  PIN S2BEG[3]
    DIRECTION OUTPUT ;
    USE SIGNAL ;
    ANTENNADIFFAREA 0.702900 ;
    PORT
      LAYER met2 ;
        RECT 124.750 0.000 125.030 0.280 ;
    END
  END S2BEG[3]
  PIN S2BEG[4]
    DIRECTION OUTPUT ;
    USE SIGNAL ;
    ANTENNADIFFAREA 0.702900 ;
    PORT
      LAYER met2 ;
        RECT 126.590 0.000 126.870 0.280 ;
    END
  END S2BEG[4]
  PIN S2BEG[5]
    DIRECTION OUTPUT ;
    USE SIGNAL ;
    ANTENNADIFFAREA 0.702900 ;
    PORT
      LAYER met2 ;
        RECT 128.430 0.000 128.710 0.280 ;
    END
  END S2BEG[5]
  PIN S2BEG[6]
    DIRECTION OUTPUT ;
    USE SIGNAL ;
    ANTENNADIFFAREA 0.702900 ;
    PORT
      LAYER met2 ;
        RECT 130.270 0.000 130.550 0.280 ;
    END
  END S2BEG[6]
  PIN S2BEG[7]
    DIRECTION OUTPUT ;
    USE SIGNAL ;
    ANTENNADIFFAREA 0.702900 ;
    PORT
      LAYER met2 ;
        RECT 132.110 0.000 132.390 0.280 ;
    END
  END S2BEG[7]
  PIN S2BEGb[0]
    DIRECTION OUTPUT ;
    USE SIGNAL ;
    ANTENNADIFFAREA 0.702900 ;
    PORT
      LAYER met2 ;
        RECT 133.950 0.000 134.230 0.280 ;
    END
  END S2BEGb[0]
  PIN S2BEGb[1]
    DIRECTION OUTPUT ;
    USE SIGNAL ;
    ANTENNADIFFAREA 0.702900 ;
    PORT
      LAYER met2 ;
        RECT 135.790 0.000 136.070 0.280 ;
    END
  END S2BEGb[1]
  PIN S2BEGb[2]
    DIRECTION OUTPUT ;
    USE SIGNAL ;
    ANTENNADIFFAREA 0.702900 ;
    PORT
      LAYER met2 ;
        RECT 137.630 0.000 137.910 0.280 ;
    END
  END S2BEGb[2]
  PIN S2BEGb[3]
    DIRECTION OUTPUT ;
    USE SIGNAL ;
    ANTENNADIFFAREA 0.702900 ;
    PORT
      LAYER met2 ;
        RECT 139.470 0.000 139.750 0.280 ;
    END
  END S2BEGb[3]
  PIN S2BEGb[4]
    DIRECTION OUTPUT ;
    USE SIGNAL ;
    ANTENNADIFFAREA 0.702900 ;
    PORT
      LAYER met2 ;
        RECT 141.310 0.000 141.590 0.280 ;
    END
  END S2BEGb[4]
  PIN S2BEGb[5]
    DIRECTION OUTPUT ;
    USE SIGNAL ;
    ANTENNADIFFAREA 0.702900 ;
    PORT
      LAYER met2 ;
        RECT 143.150 0.000 143.430 0.280 ;
    END
  END S2BEGb[5]
  PIN S2BEGb[6]
    DIRECTION OUTPUT ;
    USE SIGNAL ;
    ANTENNADIFFAREA 0.702900 ;
    PORT
      LAYER met2 ;
        RECT 144.990 0.000 145.270 0.280 ;
    END
  END S2BEGb[6]
  PIN S2BEGb[7]
    DIRECTION OUTPUT ;
    USE SIGNAL ;
    ANTENNADIFFAREA 0.702900 ;
    PORT
      LAYER met2 ;
        RECT 146.830 0.000 147.110 0.280 ;
    END
  END S2BEGb[7]
  PIN S2END[0]
    DIRECTION INPUT ;
    USE SIGNAL ;
    ANTENNAGATEAREA 1.239000 ;
    PORT
      LAYER met2 ;
        RECT 133.950 222.760 134.230 223.040 ;
    END
  END S2END[0]
  PIN S2END[1]
    DIRECTION INPUT ;
    USE SIGNAL ;
    ANTENNAGATEAREA 2.042700 ;
    ANTENNADIFFAREA 0.434700 ;
    PORT
      LAYER met2 ;
        RECT 135.790 222.760 136.070 223.040 ;
    END
  END S2END[1]
  PIN S2END[2]
    DIRECTION INPUT ;
    USE SIGNAL ;
    ANTENNAGATEAREA 1.272000 ;
    PORT
      LAYER met2 ;
        RECT 137.630 222.760 137.910 223.040 ;
    END
  END S2END[2]
  PIN S2END[3]
    DIRECTION INPUT ;
    USE SIGNAL ;
    ANTENNAGATEAREA 1.332000 ;
    PORT
      LAYER met2 ;
        RECT 139.470 222.760 139.750 223.040 ;
    END
  END S2END[3]
  PIN S2END[4]
    DIRECTION INPUT ;
    USE SIGNAL ;
    ANTENNAGATEAREA 0.795000 ;
    PORT
      LAYER met2 ;
        RECT 141.310 222.760 141.590 223.040 ;
    END
  END S2END[4]
  PIN S2END[5]
    DIRECTION INPUT ;
    USE SIGNAL ;
    ANTENNAGATEAREA 2.533800 ;
    ANTENNADIFFAREA 1.738800 ;
    PORT
      LAYER met2 ;
        RECT 143.150 222.760 143.430 223.040 ;
    END
  END S2END[5]
  PIN S2END[6]
    DIRECTION INPUT ;
    USE SIGNAL ;
    ANTENNAGATEAREA 0.795000 ;
    PORT
      LAYER met2 ;
        RECT 144.990 222.760 145.270 223.040 ;
    END
  END S2END[6]
  PIN S2END[7]
    DIRECTION INPUT ;
    USE SIGNAL ;
    ANTENNAGATEAREA 0.954000 ;
    PORT
      LAYER met2 ;
        RECT 146.830 222.760 147.110 223.040 ;
    END
  END S2END[7]
  PIN S2MID[0]
    DIRECTION INPUT ;
    USE SIGNAL ;
    ANTENNAGATEAREA 2.341800 ;
    ANTENNADIFFAREA 1.738800 ;
    PORT
      LAYER met2 ;
        RECT 119.230 222.760 119.510 223.040 ;
    END
  END S2MID[0]
  PIN S2MID[1]
    DIRECTION INPUT ;
    USE SIGNAL ;
    ANTENNAGATEAREA 0.939000 ;
    PORT
      LAYER met2 ;
        RECT 121.070 222.760 121.350 223.040 ;
    END
  END S2MID[1]
  PIN S2MID[2]
    DIRECTION INPUT ;
    USE SIGNAL ;
    ANTENNAGATEAREA 2.430300 ;
    ANTENNADIFFAREA 1.738800 ;
    PORT
      LAYER met2 ;
        RECT 122.910 222.760 123.190 223.040 ;
    END
  END S2MID[2]
  PIN S2MID[3]
    DIRECTION INPUT ;
    USE SIGNAL ;
    ANTENNAGATEAREA 1.664400 ;
    ANTENNADIFFAREA 0.869400 ;
    PORT
      LAYER met2 ;
        RECT 124.750 222.760 125.030 223.040 ;
    END
  END S2MID[3]
  PIN S2MID[4]
    DIRECTION INPUT ;
    USE SIGNAL ;
    ANTENNAGATEAREA 0.972000 ;
    PORT
      LAYER met2 ;
        RECT 126.590 222.760 126.870 223.040 ;
    END
  END S2MID[4]
  PIN S2MID[5]
    DIRECTION INPUT ;
    USE SIGNAL ;
    ANTENNAGATEAREA 0.795000 ;
    PORT
      LAYER met2 ;
        RECT 128.430 222.760 128.710 223.040 ;
    END
  END S2MID[5]
  PIN S2MID[6]
    DIRECTION INPUT ;
    USE SIGNAL ;
    ANTENNAGATEAREA 1.126200 ;
    ANTENNADIFFAREA 0.434700 ;
    PORT
      LAYER met2 ;
        RECT 130.270 222.760 130.550 223.040 ;
    END
  END S2MID[6]
  PIN S2MID[7]
    DIRECTION INPUT ;
    USE SIGNAL ;
    ANTENNAGATEAREA 0.696000 ;
    PORT
      LAYER met2 ;
        RECT 132.110 222.760 132.390 223.040 ;
    END
  END S2MID[7]
  PIN S4BEG[0]
    DIRECTION OUTPUT ;
    USE SIGNAL ;
    ANTENNADIFFAREA 0.702900 ;
    PORT
      LAYER met2 ;
        RECT 148.670 0.000 148.950 0.280 ;
    END
  END S4BEG[0]
  PIN S4BEG[10]
    DIRECTION OUTPUT ;
    USE SIGNAL ;
    ANTENNADIFFAREA 0.702900 ;
    PORT
      LAYER met2 ;
        RECT 167.070 0.000 167.350 0.280 ;
    END
  END S4BEG[10]
  PIN S4BEG[11]
    DIRECTION OUTPUT ;
    USE SIGNAL ;
    ANTENNADIFFAREA 0.702900 ;
    PORT
      LAYER met2 ;
        RECT 168.910 0.000 169.190 0.280 ;
    END
  END S4BEG[11]
  PIN S4BEG[12]
    DIRECTION OUTPUT ;
    USE SIGNAL ;
    ANTENNADIFFAREA 0.702900 ;
    PORT
      LAYER met2 ;
        RECT 170.750 0.000 171.030 0.280 ;
    END
  END S4BEG[12]
  PIN S4BEG[13]
    DIRECTION OUTPUT ;
    USE SIGNAL ;
    ANTENNADIFFAREA 0.702900 ;
    PORT
      LAYER met2 ;
        RECT 172.590 0.000 172.870 0.280 ;
    END
  END S4BEG[13]
  PIN S4BEG[14]
    DIRECTION OUTPUT ;
    USE SIGNAL ;
    ANTENNADIFFAREA 0.702900 ;
    PORT
      LAYER met2 ;
        RECT 174.430 0.000 174.710 0.280 ;
    END
  END S4BEG[14]
  PIN S4BEG[15]
    DIRECTION OUTPUT ;
    USE SIGNAL ;
    ANTENNADIFFAREA 0.702900 ;
    PORT
      LAYER met2 ;
        RECT 176.270 0.000 176.550 0.280 ;
    END
  END S4BEG[15]
  PIN S4BEG[1]
    DIRECTION OUTPUT ;
    USE SIGNAL ;
    ANTENNADIFFAREA 0.702900 ;
    PORT
      LAYER met2 ;
        RECT 150.510 0.000 150.790 0.280 ;
    END
  END S4BEG[1]
  PIN S4BEG[2]
    DIRECTION OUTPUT ;
    USE SIGNAL ;
    ANTENNADIFFAREA 0.702900 ;
    PORT
      LAYER met2 ;
        RECT 152.350 0.000 152.630 0.280 ;
    END
  END S4BEG[2]
  PIN S4BEG[3]
    DIRECTION OUTPUT ;
    USE SIGNAL ;
    ANTENNADIFFAREA 0.702900 ;
    PORT
      LAYER met2 ;
        RECT 154.190 0.000 154.470 0.280 ;
    END
  END S4BEG[3]
  PIN S4BEG[4]
    DIRECTION OUTPUT ;
    USE SIGNAL ;
    ANTENNADIFFAREA 0.702900 ;
    PORT
      LAYER met2 ;
        RECT 156.030 0.000 156.310 0.280 ;
    END
  END S4BEG[4]
  PIN S4BEG[5]
    DIRECTION OUTPUT ;
    USE SIGNAL ;
    ANTENNADIFFAREA 0.702900 ;
    PORT
      LAYER met2 ;
        RECT 157.870 0.000 158.150 0.280 ;
    END
  END S4BEG[5]
  PIN S4BEG[6]
    DIRECTION OUTPUT ;
    USE SIGNAL ;
    ANTENNADIFFAREA 0.702900 ;
    PORT
      LAYER met2 ;
        RECT 159.710 0.000 159.990 0.280 ;
    END
  END S4BEG[6]
  PIN S4BEG[7]
    DIRECTION OUTPUT ;
    USE SIGNAL ;
    ANTENNADIFFAREA 0.702900 ;
    PORT
      LAYER met2 ;
        RECT 161.550 0.000 161.830 0.280 ;
    END
  END S4BEG[7]
  PIN S4BEG[8]
    DIRECTION OUTPUT ;
    USE SIGNAL ;
    ANTENNADIFFAREA 0.702900 ;
    PORT
      LAYER met2 ;
        RECT 163.390 0.000 163.670 0.280 ;
    END
  END S4BEG[8]
  PIN S4BEG[9]
    DIRECTION OUTPUT ;
    USE SIGNAL ;
    ANTENNADIFFAREA 0.702900 ;
    PORT
      LAYER met2 ;
        RECT 165.230 0.000 165.510 0.280 ;
    END
  END S4BEG[9]
  PIN S4END[0]
    DIRECTION INPUT ;
    USE SIGNAL ;
    ANTENNAGATEAREA 3.057000 ;
    ANTENNADIFFAREA 2.173500 ;
    PORT
      LAYER met2 ;
        RECT 148.670 222.760 148.950 223.040 ;
    END
  END S4END[0]
  PIN S4END[10]
    DIRECTION INPUT ;
    USE SIGNAL ;
    ANTENNAGATEAREA 0.159000 ;
    PORT
      LAYER met2 ;
        RECT 167.070 222.760 167.350 223.040 ;
    END
  END S4END[10]
  PIN S4END[11]
    DIRECTION INPUT ;
    USE SIGNAL ;
    ANTENNAGATEAREA 0.159000 ;
    PORT
      LAYER met2 ;
        RECT 168.910 222.760 169.190 223.040 ;
    END
  END S4END[11]
  PIN S4END[12]
    DIRECTION INPUT ;
    USE SIGNAL ;
    ANTENNAGATEAREA 0.159000 ;
    PORT
      LAYER met2 ;
        RECT 170.750 222.760 171.030 223.040 ;
    END
  END S4END[12]
  PIN S4END[13]
    DIRECTION INPUT ;
    USE SIGNAL ;
    ANTENNAGATEAREA 0.159000 ;
    PORT
      LAYER met2 ;
        RECT 172.590 222.760 172.870 223.040 ;
    END
  END S4END[13]
  PIN S4END[14]
    DIRECTION INPUT ;
    USE SIGNAL ;
    ANTENNAGATEAREA 0.159000 ;
    PORT
      LAYER met2 ;
        RECT 174.430 222.760 174.710 223.040 ;
    END
  END S4END[14]
  PIN S4END[15]
    DIRECTION INPUT ;
    USE SIGNAL ;
    ANTENNAGATEAREA 0.159000 ;
    PORT
      LAYER met2 ;
        RECT 176.270 222.760 176.550 223.040 ;
    END
  END S4END[15]
  PIN S4END[1]
    DIRECTION INPUT ;
    USE SIGNAL ;
    ANTENNAGATEAREA 0.762000 ;
    PORT
      LAYER met2 ;
        RECT 150.510 222.760 150.790 223.040 ;
    END
  END S4END[1]
  PIN S4END[2]
    DIRECTION INPUT ;
    USE SIGNAL ;
    ANTENNAGATEAREA 1.131000 ;
    PORT
      LAYER met2 ;
        RECT 152.350 222.760 152.630 223.040 ;
    END
  END S4END[2]
  PIN S4END[3]
    DIRECTION INPUT ;
    USE SIGNAL ;
    ANTENNAGATEAREA 0.795000 ;
    PORT
      LAYER met2 ;
        RECT 154.190 222.760 154.470 223.040 ;
    END
  END S4END[3]
  PIN S4END[4]
    DIRECTION INPUT ;
    USE SIGNAL ;
    ANTENNAGATEAREA 0.159000 ;
    PORT
      LAYER met2 ;
        RECT 156.030 222.760 156.310 223.040 ;
    END
  END S4END[4]
  PIN S4END[5]
    DIRECTION INPUT ;
    USE SIGNAL ;
    ANTENNAGATEAREA 0.159000 ;
    PORT
      LAYER met2 ;
        RECT 157.870 222.760 158.150 223.040 ;
    END
  END S4END[5]
  PIN S4END[6]
    DIRECTION INPUT ;
    USE SIGNAL ;
    ANTENNAGATEAREA 0.159000 ;
    PORT
      LAYER met2 ;
        RECT 159.710 222.760 159.990 223.040 ;
    END
  END S4END[6]
  PIN S4END[7]
    DIRECTION INPUT ;
    USE SIGNAL ;
    ANTENNAGATEAREA 0.159000 ;
    PORT
      LAYER met2 ;
        RECT 161.550 222.760 161.830 223.040 ;
    END
  END S4END[7]
  PIN S4END[8]
    DIRECTION INPUT ;
    USE SIGNAL ;
    ANTENNAGATEAREA 0.159000 ;
    PORT
      LAYER met2 ;
        RECT 163.390 222.760 163.670 223.040 ;
    END
  END S4END[8]
  PIN S4END[9]
    DIRECTION INPUT ;
    USE SIGNAL ;
    ANTENNAGATEAREA 0.159000 ;
    PORT
      LAYER met2 ;
        RECT 165.230 222.760 165.510 223.040 ;
    END
  END S4END[9]
  PIN SS4BEG[0]
    DIRECTION OUTPUT ;
    USE SIGNAL ;
    ANTENNADIFFAREA 0.702900 ;
    PORT
      LAYER met2 ;
        RECT 178.110 0.000 178.390 0.280 ;
    END
  END SS4BEG[0]
  PIN SS4BEG[10]
    DIRECTION OUTPUT ;
    USE SIGNAL ;
    ANTENNADIFFAREA 0.702900 ;
    PORT
      LAYER met2 ;
        RECT 196.510 0.000 196.790 0.280 ;
    END
  END SS4BEG[10]
  PIN SS4BEG[11]
    DIRECTION OUTPUT ;
    USE SIGNAL ;
    ANTENNADIFFAREA 0.702900 ;
    PORT
      LAYER met2 ;
        RECT 198.350 0.000 198.630 0.280 ;
    END
  END SS4BEG[11]
  PIN SS4BEG[12]
    DIRECTION OUTPUT ;
    USE SIGNAL ;
    ANTENNADIFFAREA 0.702900 ;
    PORT
      LAYER met2 ;
        RECT 200.190 0.000 200.470 0.280 ;
    END
  END SS4BEG[12]
  PIN SS4BEG[13]
    DIRECTION OUTPUT ;
    USE SIGNAL ;
    ANTENNADIFFAREA 0.702900 ;
    PORT
      LAYER met2 ;
        RECT 202.030 0.000 202.310 0.280 ;
    END
  END SS4BEG[13]
  PIN SS4BEG[14]
    DIRECTION OUTPUT ;
    USE SIGNAL ;
    ANTENNADIFFAREA 0.702900 ;
    PORT
      LAYER met2 ;
        RECT 203.870 0.000 204.150 0.280 ;
    END
  END SS4BEG[14]
  PIN SS4BEG[15]
    DIRECTION OUTPUT ;
    USE SIGNAL ;
    ANTENNADIFFAREA 0.702900 ;
    PORT
      LAYER met2 ;
        RECT 205.710 0.000 205.990 0.280 ;
    END
  END SS4BEG[15]
  PIN SS4BEG[1]
    DIRECTION OUTPUT ;
    USE SIGNAL ;
    ANTENNADIFFAREA 0.702900 ;
    PORT
      LAYER met2 ;
        RECT 179.950 0.000 180.230 0.280 ;
    END
  END SS4BEG[1]
  PIN SS4BEG[2]
    DIRECTION OUTPUT ;
    USE SIGNAL ;
    ANTENNADIFFAREA 0.702900 ;
    PORT
      LAYER met2 ;
        RECT 181.790 0.000 182.070 0.280 ;
    END
  END SS4BEG[2]
  PIN SS4BEG[3]
    DIRECTION OUTPUT ;
    USE SIGNAL ;
    ANTENNADIFFAREA 0.702900 ;
    PORT
      LAYER met2 ;
        RECT 183.630 0.000 183.910 0.280 ;
    END
  END SS4BEG[3]
  PIN SS4BEG[4]
    DIRECTION OUTPUT ;
    USE SIGNAL ;
    ANTENNADIFFAREA 0.702900 ;
    PORT
      LAYER met2 ;
        RECT 185.470 0.000 185.750 0.280 ;
    END
  END SS4BEG[4]
  PIN SS4BEG[5]
    DIRECTION OUTPUT ;
    USE SIGNAL ;
    ANTENNADIFFAREA 0.702900 ;
    PORT
      LAYER met2 ;
        RECT 187.310 0.000 187.590 0.280 ;
    END
  END SS4BEG[5]
  PIN SS4BEG[6]
    DIRECTION OUTPUT ;
    USE SIGNAL ;
    ANTENNADIFFAREA 0.702900 ;
    PORT
      LAYER met2 ;
        RECT 189.150 0.000 189.430 0.280 ;
    END
  END SS4BEG[6]
  PIN SS4BEG[7]
    DIRECTION OUTPUT ;
    USE SIGNAL ;
    ANTENNADIFFAREA 0.702900 ;
    PORT
      LAYER met2 ;
        RECT 190.990 0.000 191.270 0.280 ;
    END
  END SS4BEG[7]
  PIN SS4BEG[8]
    DIRECTION OUTPUT ;
    USE SIGNAL ;
    ANTENNADIFFAREA 0.702900 ;
    PORT
      LAYER met2 ;
        RECT 192.830 0.000 193.110 0.280 ;
    END
  END SS4BEG[8]
  PIN SS4BEG[9]
    DIRECTION OUTPUT ;
    USE SIGNAL ;
    ANTENNADIFFAREA 0.702900 ;
    PORT
      LAYER met2 ;
        RECT 194.670 0.000 194.950 0.280 ;
    END
  END SS4BEG[9]
  PIN SS4END[0]
    DIRECTION INPUT ;
    USE SIGNAL ;
    ANTENNAGATEAREA 2.000400 ;
    ANTENNADIFFAREA 0.869400 ;
    PORT
      LAYER met2 ;
        RECT 178.110 222.760 178.390 223.040 ;
    END
  END SS4END[0]
  PIN SS4END[10]
    DIRECTION INPUT ;
    USE SIGNAL ;
    ANTENNAGATEAREA 0.159000 ;
    PORT
      LAYER met2 ;
        RECT 196.510 222.760 196.790 223.040 ;
    END
  END SS4END[10]
  PIN SS4END[11]
    DIRECTION INPUT ;
    USE SIGNAL ;
    ANTENNAGATEAREA 0.159000 ;
    PORT
      LAYER met2 ;
        RECT 198.350 222.760 198.630 223.040 ;
    END
  END SS4END[11]
  PIN SS4END[12]
    DIRECTION INPUT ;
    USE SIGNAL ;
    ANTENNAGATEAREA 0.159000 ;
    PORT
      LAYER met2 ;
        RECT 200.190 222.760 200.470 223.040 ;
    END
  END SS4END[12]
  PIN SS4END[13]
    DIRECTION INPUT ;
    USE SIGNAL ;
    ANTENNAGATEAREA 0.159000 ;
    PORT
      LAYER met2 ;
        RECT 202.030 222.760 202.310 223.040 ;
    END
  END SS4END[13]
  PIN SS4END[14]
    DIRECTION INPUT ;
    USE SIGNAL ;
    ANTENNAGATEAREA 0.159000 ;
    PORT
      LAYER met2 ;
        RECT 203.870 222.760 204.150 223.040 ;
    END
  END SS4END[14]
  PIN SS4END[15]
    DIRECTION INPUT ;
    USE SIGNAL ;
    ANTENNAGATEAREA 0.159000 ;
    PORT
      LAYER met2 ;
        RECT 205.710 222.760 205.990 223.040 ;
    END
  END SS4END[15]
  PIN SS4END[1]
    DIRECTION INPUT ;
    USE SIGNAL ;
    ANTENNAGATEAREA 0.795000 ;
    PORT
      LAYER met2 ;
        RECT 179.950 222.760 180.230 223.040 ;
    END
  END SS4END[1]
  PIN SS4END[2]
    DIRECTION INPUT ;
    USE SIGNAL ;
    ANTENNAGATEAREA 0.729000 ;
    PORT
      LAYER met2 ;
        RECT 181.790 222.760 182.070 223.040 ;
    END
  END SS4END[2]
  PIN SS4END[3]
    DIRECTION INPUT ;
    USE SIGNAL ;
    ANTENNAGATEAREA 0.762000 ;
    PORT
      LAYER met2 ;
        RECT 183.630 222.760 183.910 223.040 ;
    END
  END SS4END[3]
  PIN SS4END[4]
    DIRECTION INPUT ;
    USE SIGNAL ;
    ANTENNAGATEAREA 0.159000 ;
    PORT
      LAYER met2 ;
        RECT 185.470 222.760 185.750 223.040 ;
    END
  END SS4END[4]
  PIN SS4END[5]
    DIRECTION INPUT ;
    USE SIGNAL ;
    ANTENNAGATEAREA 0.159000 ;
    PORT
      LAYER met2 ;
        RECT 187.310 222.760 187.590 223.040 ;
    END
  END SS4END[5]
  PIN SS4END[6]
    DIRECTION INPUT ;
    USE SIGNAL ;
    ANTENNAGATEAREA 0.159000 ;
    PORT
      LAYER met2 ;
        RECT 189.150 222.760 189.430 223.040 ;
    END
  END SS4END[6]
  PIN SS4END[7]
    DIRECTION INPUT ;
    USE SIGNAL ;
    ANTENNAGATEAREA 0.159000 ;
    PORT
      LAYER met2 ;
        RECT 190.990 222.760 191.270 223.040 ;
    END
  END SS4END[7]
  PIN SS4END[8]
    DIRECTION INPUT ;
    USE SIGNAL ;
    ANTENNAGATEAREA 0.159000 ;
    PORT
      LAYER met2 ;
        RECT 192.830 222.760 193.110 223.040 ;
    END
  END SS4END[8]
  PIN SS4END[9]
    DIRECTION INPUT ;
    USE SIGNAL ;
    ANTENNAGATEAREA 0.159000 ;
    PORT
      LAYER met2 ;
        RECT 194.670 222.760 194.950 223.040 ;
    END
  END SS4END[9]
  PIN VGND
    DIRECTION INOUT ;
    USE GROUND ;
    PORT
      LAYER met4 ;
        RECT 12.260 0.000 13.860 223.040 ;
    END
    PORT
      LAYER met4 ;
        RECT 42.260 0.000 43.860 223.040 ;
    END
    PORT
      LAYER met4 ;
        RECT 72.260 0.000 73.860 223.040 ;
    END
    PORT
      LAYER met4 ;
        RECT 102.260 0.000 103.860 223.040 ;
    END
    PORT
      LAYER met4 ;
        RECT 132.260 0.000 133.860 223.040 ;
    END
    PORT
      LAYER met4 ;
        RECT 162.260 0.000 163.860 223.040 ;
    END
    PORT
      LAYER met4 ;
        RECT 192.260 0.000 193.860 223.040 ;
    END
    PORT
      LAYER met4 ;
        RECT 222.260 0.000 223.860 223.040 ;
    END
  END VGND
  PIN VPWR
    DIRECTION INOUT ;
    USE POWER ;
    PORT
      LAYER met4 ;
        RECT 6.960 0.000 8.560 223.040 ;
    END
    PORT
      LAYER met4 ;
        RECT 36.960 0.000 38.560 223.040 ;
    END
    PORT
      LAYER met4 ;
        RECT 66.960 0.000 68.560 223.040 ;
    END
    PORT
      LAYER met4 ;
        RECT 96.960 0.000 98.560 223.040 ;
    END
    PORT
      LAYER met4 ;
        RECT 126.960 0.000 128.560 223.040 ;
    END
    PORT
      LAYER met4 ;
        RECT 156.960 0.000 158.560 223.040 ;
    END
    PORT
      LAYER met4 ;
        RECT 186.960 0.000 188.560 223.040 ;
    END
    PORT
      LAYER met4 ;
        RECT 216.960 0.000 218.560 223.040 ;
    END
    PORT
      LAYER met4 ;
        RECT 246.960 0.000 248.560 223.040 ;
    END
  END VPWR
  PIN W1BEG[0]
    DIRECTION OUTPUT ;
    USE SIGNAL ;
    ANTENNADIFFAREA 0.702900 ;
    PORT
      LAYER met3 ;
        RECT 0.000 24.520 0.600 25.120 ;
    END
  END W1BEG[0]
  PIN W1BEG[1]
    DIRECTION OUTPUT ;
    USE SIGNAL ;
    ANTENNADIFFAREA 0.702900 ;
    PORT
      LAYER met3 ;
        RECT 0.000 25.880 0.600 26.480 ;
    END
  END W1BEG[1]
  PIN W1BEG[2]
    DIRECTION OUTPUT ;
    USE SIGNAL ;
    ANTENNADIFFAREA 0.702900 ;
    PORT
      LAYER met3 ;
        RECT 0.000 27.240 0.600 27.840 ;
    END
  END W1BEG[2]
  PIN W1BEG[3]
    DIRECTION OUTPUT ;
    USE SIGNAL ;
    ANTENNADIFFAREA 0.702900 ;
    PORT
      LAYER met3 ;
        RECT 0.000 28.600 0.600 29.200 ;
    END
  END W1BEG[3]
  PIN W1END[0]
    DIRECTION INPUT ;
    USE SIGNAL ;
    ANTENNAGATEAREA 2.234400 ;
    ANTENNADIFFAREA 0.869400 ;
    PORT
      LAYER met3 ;
        RECT 251.480 24.520 252.080 25.120 ;
    END
  END W1END[0]
  PIN W1END[1]
    DIRECTION INPUT ;
    USE SIGNAL ;
    ANTENNAGATEAREA 2.735100 ;
    ANTENNADIFFAREA 1.304100 ;
    PORT
      LAYER met3 ;
        RECT 251.480 25.880 252.080 26.480 ;
    END
  END W1END[1]
  PIN W1END[2]
    DIRECTION INPUT ;
    USE SIGNAL ;
    ANTENNAGATEAREA 2.987100 ;
    ANTENNADIFFAREA 1.304100 ;
    PORT
      LAYER met3 ;
        RECT 251.480 27.240 252.080 27.840 ;
    END
  END W1END[2]
  PIN W1END[3]
    DIRECTION INPUT ;
    USE SIGNAL ;
    ANTENNAGATEAREA 1.749000 ;
    PORT
      LAYER met3 ;
        RECT 251.480 28.600 252.080 29.200 ;
    END
  END W1END[3]
  PIN W2BEG[0]
    DIRECTION OUTPUT ;
    USE SIGNAL ;
    ANTENNADIFFAREA 0.702900 ;
    PORT
      LAYER met3 ;
        RECT 0.000 29.960 0.600 30.560 ;
    END
  END W2BEG[0]
  PIN W2BEG[1]
    DIRECTION OUTPUT ;
    USE SIGNAL ;
    ANTENNADIFFAREA 0.702900 ;
    PORT
      LAYER met3 ;
        RECT 0.000 31.320 0.600 31.920 ;
    END
  END W2BEG[1]
  PIN W2BEG[2]
    DIRECTION OUTPUT ;
    USE SIGNAL ;
    ANTENNADIFFAREA 0.702900 ;
    PORT
      LAYER met3 ;
        RECT 0.000 32.680 0.600 33.280 ;
    END
  END W2BEG[2]
  PIN W2BEG[3]
    DIRECTION OUTPUT ;
    USE SIGNAL ;
    ANTENNADIFFAREA 0.702900 ;
    PORT
      LAYER met3 ;
        RECT 0.000 34.040 0.600 34.640 ;
    END
  END W2BEG[3]
  PIN W2BEG[4]
    DIRECTION OUTPUT ;
    USE SIGNAL ;
    ANTENNADIFFAREA 0.702900 ;
    PORT
      LAYER met3 ;
        RECT 0.000 35.400 0.600 36.000 ;
    END
  END W2BEG[4]
  PIN W2BEG[5]
    DIRECTION OUTPUT ;
    USE SIGNAL ;
    ANTENNADIFFAREA 0.702900 ;
    PORT
      LAYER met3 ;
        RECT 0.000 36.760 0.600 37.360 ;
    END
  END W2BEG[5]
  PIN W2BEG[6]
    DIRECTION OUTPUT ;
    USE SIGNAL ;
    ANTENNADIFFAREA 0.702900 ;
    PORT
      LAYER met3 ;
        RECT 0.000 38.120 0.600 38.720 ;
    END
  END W2BEG[6]
  PIN W2BEG[7]
    DIRECTION OUTPUT ;
    USE SIGNAL ;
    ANTENNADIFFAREA 0.702900 ;
    PORT
      LAYER met3 ;
        RECT 0.000 39.480 0.600 40.080 ;
    END
  END W2BEG[7]
  PIN W2BEGb[0]
    DIRECTION OUTPUT ;
    USE SIGNAL ;
    ANTENNADIFFAREA 0.702900 ;
    PORT
      LAYER met3 ;
        RECT 0.000 40.840 0.600 41.440 ;
    END
  END W2BEGb[0]
  PIN W2BEGb[1]
    DIRECTION OUTPUT ;
    USE SIGNAL ;
    ANTENNADIFFAREA 0.702900 ;
    PORT
      LAYER met3 ;
        RECT 0.000 42.200 0.600 42.800 ;
    END
  END W2BEGb[1]
  PIN W2BEGb[2]
    DIRECTION OUTPUT ;
    USE SIGNAL ;
    ANTENNADIFFAREA 0.702900 ;
    PORT
      LAYER met3 ;
        RECT 0.000 43.560 0.600 44.160 ;
    END
  END W2BEGb[2]
  PIN W2BEGb[3]
    DIRECTION OUTPUT ;
    USE SIGNAL ;
    ANTENNADIFFAREA 0.702900 ;
    PORT
      LAYER met3 ;
        RECT 0.000 44.920 0.600 45.520 ;
    END
  END W2BEGb[3]
  PIN W2BEGb[4]
    DIRECTION OUTPUT ;
    USE SIGNAL ;
    ANTENNADIFFAREA 0.702900 ;
    PORT
      LAYER met3 ;
        RECT 0.000 46.280 0.600 46.880 ;
    END
  END W2BEGb[4]
  PIN W2BEGb[5]
    DIRECTION OUTPUT ;
    USE SIGNAL ;
    ANTENNADIFFAREA 0.702900 ;
    PORT
      LAYER met3 ;
        RECT 0.000 47.640 0.600 48.240 ;
    END
  END W2BEGb[5]
  PIN W2BEGb[6]
    DIRECTION OUTPUT ;
    USE SIGNAL ;
    ANTENNADIFFAREA 0.702900 ;
    PORT
      LAYER met3 ;
        RECT 0.000 49.000 0.600 49.600 ;
    END
  END W2BEGb[6]
  PIN W2BEGb[7]
    DIRECTION OUTPUT ;
    USE SIGNAL ;
    ANTENNADIFFAREA 0.702900 ;
    PORT
      LAYER met3 ;
        RECT 0.000 50.360 0.600 50.960 ;
    END
  END W2BEGb[7]
  PIN W2END[0]
    DIRECTION INPUT ;
    USE SIGNAL ;
    ANTENNAGATEAREA 0.318000 ;
    PORT
      LAYER met3 ;
        RECT 251.480 40.840 252.080 41.440 ;
    END
  END W2END[0]
  PIN W2END[1]
    DIRECTION INPUT ;
    USE SIGNAL ;
    ANTENNAGATEAREA 1.290000 ;
    PORT
      LAYER met3 ;
        RECT 251.480 42.200 252.080 42.800 ;
    END
  END W2END[1]
  PIN W2END[2]
    DIRECTION INPUT ;
    USE SIGNAL ;
    ANTENNAGATEAREA 0.921000 ;
    PORT
      LAYER met3 ;
        RECT 251.480 43.560 252.080 44.160 ;
    END
  END W2END[2]
  PIN W2END[3]
    DIRECTION INPUT ;
    USE SIGNAL ;
    ANTENNAGATEAREA 0.954000 ;
    PORT
      LAYER met3 ;
        RECT 251.480 44.920 252.080 45.520 ;
    END
  END W2END[3]
  PIN W2END[4]
    DIRECTION INPUT ;
    USE SIGNAL ;
    ANTENNAGATEAREA 1.113000 ;
    PORT
      LAYER met3 ;
        RECT 251.480 46.280 252.080 46.880 ;
    END
  END W2END[4]
  PIN W2END[5]
    DIRECTION INPUT ;
    USE SIGNAL ;
    ANTENNAGATEAREA 1.187400 ;
    ANTENNADIFFAREA 0.869400 ;
    PORT
      LAYER met3 ;
        RECT 251.480 47.640 252.080 48.240 ;
    END
  END W2END[5]
  PIN W2END[6]
    DIRECTION INPUT ;
    USE SIGNAL ;
    ANTENNAGATEAREA 1.187400 ;
    ANTENNADIFFAREA 0.869400 ;
    PORT
      LAYER met3 ;
        RECT 251.480 49.000 252.080 49.600 ;
    END
  END W2END[6]
  PIN W2END[7]
    DIRECTION INPUT ;
    USE SIGNAL ;
    ANTENNAGATEAREA 0.911700 ;
    ANTENNADIFFAREA 0.434700 ;
    PORT
      LAYER met3 ;
        RECT 251.480 50.360 252.080 50.960 ;
    END
  END W2END[7]
  PIN W2MID[0]
    DIRECTION INPUT ;
    USE SIGNAL ;
    ANTENNAGATEAREA 0.636000 ;
    PORT
      LAYER met3 ;
        RECT 251.480 29.960 252.080 30.560 ;
    END
  END W2MID[0]
  PIN W2MID[1]
    DIRECTION INPUT ;
    USE SIGNAL ;
    ANTENNAGATEAREA 1.434000 ;
    PORT
      LAYER met3 ;
        RECT 251.480 31.320 252.080 31.920 ;
    END
  END W2MID[1]
  PIN W2MID[2]
    DIRECTION INPUT ;
    USE SIGNAL ;
    ANTENNAGATEAREA 2.463300 ;
    ANTENNADIFFAREA 1.738800 ;
    PORT
      LAYER met3 ;
        RECT 251.480 32.680 252.080 33.280 ;
    END
  END W2MID[2]
  PIN W2MID[3]
    DIRECTION INPUT ;
    USE SIGNAL ;
    ANTENNAGATEAREA 1.229700 ;
    ANTENNADIFFAREA 0.434700 ;
    PORT
      LAYER met3 ;
        RECT 251.480 34.040 252.080 34.640 ;
    END
  END W2MID[3]
  PIN W2MID[4]
    DIRECTION INPUT ;
    USE SIGNAL ;
    ANTENNAGATEAREA 1.841400 ;
    ANTENNADIFFAREA 0.869400 ;
    PORT
      LAYER met3 ;
        RECT 251.480 35.400 252.080 36.000 ;
    END
  END W2MID[4]
  PIN W2MID[5]
    DIRECTION INPUT ;
    USE SIGNAL ;
    ANTENNAGATEAREA 2.968500 ;
    ANTENNADIFFAREA 2.173500 ;
    PORT
      LAYER met3 ;
        RECT 251.480 36.760 252.080 37.360 ;
    END
  END W2MID[5]
  PIN W2MID[6]
    DIRECTION INPUT ;
    USE SIGNAL ;
    ANTENNAGATEAREA 2.341800 ;
    ANTENNADIFFAREA 1.738800 ;
    PORT
      LAYER met3 ;
        RECT 251.480 38.120 252.080 38.720 ;
    END
  END W2MID[6]
  PIN W2MID[7]
    DIRECTION INPUT ;
    USE SIGNAL ;
    ANTENNAGATEAREA 1.565400 ;
    ANTENNADIFFAREA 0.869400 ;
    PORT
      LAYER met3 ;
        RECT 251.480 39.480 252.080 40.080 ;
    END
  END W2MID[7]
  PIN W6BEG[0]
    DIRECTION OUTPUT ;
    USE SIGNAL ;
    ANTENNADIFFAREA 0.702900 ;
    PORT
      LAYER met3 ;
        RECT 0.000 73.480 0.600 74.080 ;
    END
  END W6BEG[0]
  PIN W6BEG[10]
    DIRECTION OUTPUT ;
    USE SIGNAL ;
    ANTENNADIFFAREA 0.702900 ;
    PORT
      LAYER met3 ;
        RECT 0.000 87.080 0.600 87.680 ;
    END
  END W6BEG[10]
  PIN W6BEG[11]
    DIRECTION OUTPUT ;
    USE SIGNAL ;
    ANTENNADIFFAREA 0.702900 ;
    PORT
      LAYER met3 ;
        RECT 0.000 88.440 0.600 89.040 ;
    END
  END W6BEG[11]
  PIN W6BEG[1]
    DIRECTION OUTPUT ;
    USE SIGNAL ;
    ANTENNADIFFAREA 0.702900 ;
    PORT
      LAYER met3 ;
        RECT 0.000 74.840 0.600 75.440 ;
    END
  END W6BEG[1]
  PIN W6BEG[2]
    DIRECTION OUTPUT ;
    USE SIGNAL ;
    ANTENNADIFFAREA 0.702900 ;
    PORT
      LAYER met3 ;
        RECT 0.000 76.200 0.600 76.800 ;
    END
  END W6BEG[2]
  PIN W6BEG[3]
    DIRECTION OUTPUT ;
    USE SIGNAL ;
    ANTENNADIFFAREA 0.702900 ;
    PORT
      LAYER met3 ;
        RECT 0.000 77.560 0.600 78.160 ;
    END
  END W6BEG[3]
  PIN W6BEG[4]
    DIRECTION OUTPUT ;
    USE SIGNAL ;
    ANTENNADIFFAREA 0.702900 ;
    PORT
      LAYER met3 ;
        RECT 0.000 78.920 0.600 79.520 ;
    END
  END W6BEG[4]
  PIN W6BEG[5]
    DIRECTION OUTPUT ;
    USE SIGNAL ;
    ANTENNADIFFAREA 0.702900 ;
    PORT
      LAYER met3 ;
        RECT 0.000 80.280 0.600 80.880 ;
    END
  END W6BEG[5]
  PIN W6BEG[6]
    DIRECTION OUTPUT ;
    USE SIGNAL ;
    ANTENNADIFFAREA 0.702900 ;
    PORT
      LAYER met3 ;
        RECT 0.000 81.640 0.600 82.240 ;
    END
  END W6BEG[6]
  PIN W6BEG[7]
    DIRECTION OUTPUT ;
    USE SIGNAL ;
    ANTENNADIFFAREA 0.702900 ;
    PORT
      LAYER met3 ;
        RECT 0.000 83.000 0.600 83.600 ;
    END
  END W6BEG[7]
  PIN W6BEG[8]
    DIRECTION OUTPUT ;
    USE SIGNAL ;
    ANTENNADIFFAREA 0.702900 ;
    PORT
      LAYER met3 ;
        RECT 0.000 84.360 0.600 84.960 ;
    END
  END W6BEG[8]
  PIN W6BEG[9]
    DIRECTION OUTPUT ;
    USE SIGNAL ;
    ANTENNADIFFAREA 0.702900 ;
    PORT
      LAYER met3 ;
        RECT 0.000 85.720 0.600 86.320 ;
    END
  END W6BEG[9]
  PIN W6END[0]
    DIRECTION INPUT ;
    USE SIGNAL ;
    ANTENNAGATEAREA 2.085000 ;
    PORT
      LAYER met3 ;
        RECT 251.480 73.480 252.080 74.080 ;
    END
  END W6END[0]
  PIN W6END[10]
    DIRECTION INPUT ;
    USE SIGNAL ;
    ANTENNAGATEAREA 0.159000 ;
    PORT
      LAYER met3 ;
        RECT 251.480 87.080 252.080 87.680 ;
    END
  END W6END[10]
  PIN W6END[11]
    DIRECTION INPUT ;
    USE SIGNAL ;
    ANTENNAGATEAREA 0.159000 ;
    PORT
      LAYER met3 ;
        RECT 251.480 88.440 252.080 89.040 ;
    END
  END W6END[11]
  PIN W6END[1]
    DIRECTION INPUT ;
    USE SIGNAL ;
    ANTENNAGATEAREA 2.618400 ;
    ANTENNADIFFAREA 0.869400 ;
    PORT
      LAYER met3 ;
        RECT 251.480 74.840 252.080 75.440 ;
    END
  END W6END[1]
  PIN W6END[2]
    DIRECTION INPUT ;
    USE SIGNAL ;
    ANTENNAGATEAREA 0.159000 ;
    PORT
      LAYER met3 ;
        RECT 251.480 76.200 252.080 76.800 ;
    END
  END W6END[2]
  PIN W6END[3]
    DIRECTION INPUT ;
    USE SIGNAL ;
    ANTENNAGATEAREA 0.159000 ;
    PORT
      LAYER met3 ;
        RECT 251.480 77.560 252.080 78.160 ;
    END
  END W6END[3]
  PIN W6END[4]
    DIRECTION INPUT ;
    USE SIGNAL ;
    ANTENNAGATEAREA 0.159000 ;
    PORT
      LAYER met3 ;
        RECT 251.480 78.920 252.080 79.520 ;
    END
  END W6END[4]
  PIN W6END[5]
    DIRECTION INPUT ;
    USE SIGNAL ;
    ANTENNAGATEAREA 0.159000 ;
    PORT
      LAYER met3 ;
        RECT 251.480 80.280 252.080 80.880 ;
    END
  END W6END[5]
  PIN W6END[6]
    DIRECTION INPUT ;
    USE SIGNAL ;
    ANTENNAGATEAREA 0.159000 ;
    PORT
      LAYER met3 ;
        RECT 251.480 81.640 252.080 82.240 ;
    END
  END W6END[6]
  PIN W6END[7]
    DIRECTION INPUT ;
    USE SIGNAL ;
    ANTENNAGATEAREA 0.159000 ;
    PORT
      LAYER met3 ;
        RECT 251.480 83.000 252.080 83.600 ;
    END
  END W6END[7]
  PIN W6END[8]
    DIRECTION INPUT ;
    USE SIGNAL ;
    ANTENNAGATEAREA 0.159000 ;
    PORT
      LAYER met3 ;
        RECT 251.480 84.360 252.080 84.960 ;
    END
  END W6END[8]
  PIN W6END[9]
    DIRECTION INPUT ;
    USE SIGNAL ;
    ANTENNAGATEAREA 0.159000 ;
    PORT
      LAYER met3 ;
        RECT 251.480 85.720 252.080 86.320 ;
    END
  END W6END[9]
  PIN WW4BEG[0]
    DIRECTION OUTPUT ;
    USE SIGNAL ;
    ANTENNADIFFAREA 0.702900 ;
    PORT
      LAYER met3 ;
        RECT 0.000 51.720 0.600 52.320 ;
    END
  END WW4BEG[0]
  PIN WW4BEG[10]
    DIRECTION OUTPUT ;
    USE SIGNAL ;
    ANTENNADIFFAREA 0.702900 ;
    PORT
      LAYER met3 ;
        RECT 0.000 65.320 0.600 65.920 ;
    END
  END WW4BEG[10]
  PIN WW4BEG[11]
    DIRECTION OUTPUT ;
    USE SIGNAL ;
    ANTENNADIFFAREA 0.702900 ;
    PORT
      LAYER met3 ;
        RECT 0.000 66.680 0.600 67.280 ;
    END
  END WW4BEG[11]
  PIN WW4BEG[12]
    DIRECTION OUTPUT ;
    USE SIGNAL ;
    ANTENNADIFFAREA 0.702900 ;
    PORT
      LAYER met3 ;
        RECT 0.000 68.040 0.600 68.640 ;
    END
  END WW4BEG[12]
  PIN WW4BEG[13]
    DIRECTION OUTPUT ;
    USE SIGNAL ;
    ANTENNADIFFAREA 0.702900 ;
    PORT
      LAYER met3 ;
        RECT 0.000 69.400 0.600 70.000 ;
    END
  END WW4BEG[13]
  PIN WW4BEG[14]
    DIRECTION OUTPUT ;
    USE SIGNAL ;
    ANTENNADIFFAREA 0.702900 ;
    PORT
      LAYER met3 ;
        RECT 0.000 70.760 0.600 71.360 ;
    END
  END WW4BEG[14]
  PIN WW4BEG[15]
    DIRECTION OUTPUT ;
    USE SIGNAL ;
    ANTENNADIFFAREA 0.702900 ;
    PORT
      LAYER met3 ;
        RECT 0.000 72.120 0.600 72.720 ;
    END
  END WW4BEG[15]
  PIN WW4BEG[1]
    DIRECTION OUTPUT ;
    USE SIGNAL ;
    ANTENNADIFFAREA 0.702900 ;
    PORT
      LAYER met3 ;
        RECT 0.000 53.080 0.600 53.680 ;
    END
  END WW4BEG[1]
  PIN WW4BEG[2]
    DIRECTION OUTPUT ;
    USE SIGNAL ;
    ANTENNADIFFAREA 0.702900 ;
    PORT
      LAYER met3 ;
        RECT 0.000 54.440 0.600 55.040 ;
    END
  END WW4BEG[2]
  PIN WW4BEG[3]
    DIRECTION OUTPUT ;
    USE SIGNAL ;
    ANTENNADIFFAREA 0.702900 ;
    PORT
      LAYER met3 ;
        RECT 0.000 55.800 0.600 56.400 ;
    END
  END WW4BEG[3]
  PIN WW4BEG[4]
    DIRECTION OUTPUT ;
    USE SIGNAL ;
    ANTENNADIFFAREA 0.702900 ;
    PORT
      LAYER met3 ;
        RECT 0.000 57.160 0.600 57.760 ;
    END
  END WW4BEG[4]
  PIN WW4BEG[5]
    DIRECTION OUTPUT ;
    USE SIGNAL ;
    ANTENNADIFFAREA 0.702900 ;
    PORT
      LAYER met3 ;
        RECT 0.000 58.520 0.600 59.120 ;
    END
  END WW4BEG[5]
  PIN WW4BEG[6]
    DIRECTION OUTPUT ;
    USE SIGNAL ;
    ANTENNADIFFAREA 0.702900 ;
    PORT
      LAYER met3 ;
        RECT 0.000 59.880 0.600 60.480 ;
    END
  END WW4BEG[6]
  PIN WW4BEG[7]
    DIRECTION OUTPUT ;
    USE SIGNAL ;
    ANTENNADIFFAREA 0.702900 ;
    PORT
      LAYER met3 ;
        RECT 0.000 61.240 0.600 61.840 ;
    END
  END WW4BEG[7]
  PIN WW4BEG[8]
    DIRECTION OUTPUT ;
    USE SIGNAL ;
    ANTENNADIFFAREA 0.702900 ;
    PORT
      LAYER met3 ;
        RECT 0.000 62.600 0.600 63.200 ;
    END
  END WW4BEG[8]
  PIN WW4BEG[9]
    DIRECTION OUTPUT ;
    USE SIGNAL ;
    ANTENNADIFFAREA 0.702900 ;
    PORT
      LAYER met3 ;
        RECT 0.000 63.960 0.600 64.560 ;
    END
  END WW4BEG[9]
  PIN WW4END[0]
    DIRECTION INPUT ;
    USE SIGNAL ;
    ANTENNAGATEAREA 2.374800 ;
    ANTENNADIFFAREA 1.738800 ;
    PORT
      LAYER met3 ;
        RECT 251.480 51.720 252.080 52.320 ;
    END
  END WW4END[0]
  PIN WW4END[10]
    DIRECTION INPUT ;
    USE SIGNAL ;
    ANTENNAGATEAREA 0.593700 ;
    ANTENNADIFFAREA 0.434700 ;
    PORT
      LAYER met3 ;
        RECT 251.480 65.320 252.080 65.920 ;
    END
  END WW4END[10]
  PIN WW4END[11]
    DIRECTION INPUT ;
    USE SIGNAL ;
    ANTENNAGATEAREA 0.593700 ;
    ANTENNADIFFAREA 0.434700 ;
    PORT
      LAYER met3 ;
        RECT 251.480 66.680 252.080 67.280 ;
    END
  END WW4END[11]
  PIN WW4END[12]
    DIRECTION INPUT ;
    USE SIGNAL ;
    ANTENNAGATEAREA 0.593700 ;
    ANTENNADIFFAREA 0.434700 ;
    PORT
      LAYER met3 ;
        RECT 251.480 68.040 252.080 68.640 ;
    END
  END WW4END[12]
  PIN WW4END[13]
    DIRECTION INPUT ;
    USE SIGNAL ;
    ANTENNAGATEAREA 0.159000 ;
    PORT
      LAYER met3 ;
        RECT 251.480 69.400 252.080 70.000 ;
    END
  END WW4END[13]
  PIN WW4END[14]
    DIRECTION INPUT ;
    USE SIGNAL ;
    ANTENNAGATEAREA 0.593700 ;
    ANTENNADIFFAREA 0.434700 ;
    PORT
      LAYER met3 ;
        RECT 251.480 70.760 252.080 71.360 ;
    END
  END WW4END[14]
  PIN WW4END[15]
    DIRECTION INPUT ;
    USE SIGNAL ;
    ANTENNAGATEAREA 0.593700 ;
    ANTENNADIFFAREA 0.434700 ;
    PORT
      LAYER met3 ;
        RECT 251.480 72.120 252.080 72.720 ;
    END
  END WW4END[15]
  PIN WW4END[1]
    DIRECTION INPUT ;
    USE SIGNAL ;
    ANTENNAGATEAREA 2.374800 ;
    ANTENNADIFFAREA 1.738800 ;
    PORT
      LAYER met3 ;
        RECT 251.480 53.080 252.080 53.680 ;
    END
  END WW4END[1]
  PIN WW4END[2]
    DIRECTION INPUT ;
    USE SIGNAL ;
    ANTENNAGATEAREA 0.636000 ;
    PORT
      LAYER met3 ;
        RECT 251.480 54.440 252.080 55.040 ;
    END
  END WW4END[2]
  PIN WW4END[3]
    DIRECTION INPUT ;
    USE SIGNAL ;
    ANTENNAGATEAREA 2.276100 ;
    ANTENNADIFFAREA 1.304100 ;
    PORT
      LAYER met3 ;
        RECT 251.480 55.800 252.080 56.400 ;
    END
  END WW4END[3]
  PIN WW4END[4]
    DIRECTION INPUT ;
    USE SIGNAL ;
    ANTENNAGATEAREA 0.593700 ;
    ANTENNADIFFAREA 0.434700 ;
    PORT
      LAYER met3 ;
        RECT 251.480 57.160 252.080 57.760 ;
    END
  END WW4END[4]
  PIN WW4END[5]
    DIRECTION INPUT ;
    USE SIGNAL ;
    ANTENNAGATEAREA 0.593700 ;
    ANTENNADIFFAREA 0.434700 ;
    PORT
      LAYER met3 ;
        RECT 251.480 58.520 252.080 59.120 ;
    END
  END WW4END[5]
  PIN WW4END[6]
    DIRECTION INPUT ;
    USE SIGNAL ;
    ANTENNAGATEAREA 0.593700 ;
    ANTENNADIFFAREA 0.434700 ;
    PORT
      LAYER met3 ;
        RECT 251.480 59.880 252.080 60.480 ;
    END
  END WW4END[6]
  PIN WW4END[7]
    DIRECTION INPUT ;
    USE SIGNAL ;
    ANTENNAGATEAREA 1.028400 ;
    ANTENNADIFFAREA 0.869400 ;
    PORT
      LAYER met3 ;
        RECT 251.480 61.240 252.080 61.840 ;
    END
  END WW4END[7]
  PIN WW4END[8]
    DIRECTION INPUT ;
    USE SIGNAL ;
    ANTENNAGATEAREA 0.593700 ;
    ANTENNADIFFAREA 0.434700 ;
    PORT
      LAYER met3 ;
        RECT 251.480 62.600 252.080 63.200 ;
    END
  END WW4END[8]
  PIN WW4END[9]
    DIRECTION INPUT ;
    USE SIGNAL ;
    ANTENNAGATEAREA 0.593700 ;
    ANTENNADIFFAREA 0.434700 ;
    PORT
      LAYER met3 ;
        RECT 251.480 63.960 252.080 64.560 ;
    END
  END WW4END[9]
  OBS
      LAYER nwell ;
        RECT 2.570 2.635 249.510 220.405 ;
      LAYER li1 ;
        RECT 2.760 2.635 249.320 220.405 ;
      LAYER met1 ;
        RECT 0.530 0.380 251.550 222.660 ;
      LAYER met2 ;
        RECT 0.550 222.480 8.550 222.770 ;
        RECT 9.390 222.480 10.390 222.770 ;
        RECT 11.230 222.480 12.230 222.770 ;
        RECT 13.070 222.480 14.070 222.770 ;
        RECT 14.910 222.480 15.910 222.770 ;
        RECT 16.750 222.480 17.750 222.770 ;
        RECT 18.590 222.480 19.590 222.770 ;
        RECT 20.430 222.480 21.430 222.770 ;
        RECT 22.270 222.480 23.270 222.770 ;
        RECT 24.110 222.480 25.110 222.770 ;
        RECT 25.950 222.480 26.950 222.770 ;
        RECT 27.790 222.480 28.790 222.770 ;
        RECT 29.630 222.480 30.630 222.770 ;
        RECT 31.470 222.480 32.470 222.770 ;
        RECT 33.310 222.480 34.310 222.770 ;
        RECT 35.150 222.480 36.150 222.770 ;
        RECT 36.990 222.480 37.990 222.770 ;
        RECT 38.830 222.480 39.830 222.770 ;
        RECT 40.670 222.480 41.670 222.770 ;
        RECT 42.510 222.480 43.510 222.770 ;
        RECT 44.350 222.480 45.350 222.770 ;
        RECT 46.190 222.480 47.190 222.770 ;
        RECT 48.030 222.480 49.030 222.770 ;
        RECT 49.870 222.480 50.870 222.770 ;
        RECT 51.710 222.480 52.710 222.770 ;
        RECT 53.550 222.480 54.550 222.770 ;
        RECT 55.390 222.480 56.390 222.770 ;
        RECT 57.230 222.480 58.230 222.770 ;
        RECT 59.070 222.480 60.070 222.770 ;
        RECT 60.910 222.480 61.910 222.770 ;
        RECT 62.750 222.480 63.750 222.770 ;
        RECT 64.590 222.480 65.590 222.770 ;
        RECT 66.430 222.480 67.430 222.770 ;
        RECT 68.270 222.480 69.270 222.770 ;
        RECT 70.110 222.480 71.110 222.770 ;
        RECT 71.950 222.480 72.950 222.770 ;
        RECT 73.790 222.480 74.790 222.770 ;
        RECT 75.630 222.480 76.630 222.770 ;
        RECT 77.470 222.480 78.470 222.770 ;
        RECT 79.310 222.480 80.310 222.770 ;
        RECT 81.150 222.480 82.150 222.770 ;
        RECT 82.990 222.480 83.990 222.770 ;
        RECT 84.830 222.480 85.830 222.770 ;
        RECT 86.670 222.480 87.670 222.770 ;
        RECT 88.510 222.480 89.510 222.770 ;
        RECT 90.350 222.480 91.350 222.770 ;
        RECT 92.190 222.480 93.190 222.770 ;
        RECT 94.030 222.480 95.030 222.770 ;
        RECT 95.870 222.480 96.870 222.770 ;
        RECT 97.710 222.480 98.710 222.770 ;
        RECT 99.550 222.480 100.550 222.770 ;
        RECT 101.390 222.480 102.390 222.770 ;
        RECT 103.230 222.480 104.230 222.770 ;
        RECT 105.070 222.480 106.070 222.770 ;
        RECT 106.910 222.480 107.910 222.770 ;
        RECT 108.750 222.480 109.750 222.770 ;
        RECT 110.590 222.480 111.590 222.770 ;
        RECT 112.430 222.480 113.430 222.770 ;
        RECT 114.270 222.480 115.270 222.770 ;
        RECT 116.110 222.480 117.110 222.770 ;
        RECT 117.950 222.480 118.950 222.770 ;
        RECT 119.790 222.480 120.790 222.770 ;
        RECT 121.630 222.480 122.630 222.770 ;
        RECT 123.470 222.480 124.470 222.770 ;
        RECT 125.310 222.480 126.310 222.770 ;
        RECT 127.150 222.480 128.150 222.770 ;
        RECT 128.990 222.480 129.990 222.770 ;
        RECT 130.830 222.480 131.830 222.770 ;
        RECT 132.670 222.480 133.670 222.770 ;
        RECT 134.510 222.480 135.510 222.770 ;
        RECT 136.350 222.480 137.350 222.770 ;
        RECT 138.190 222.480 139.190 222.770 ;
        RECT 140.030 222.480 141.030 222.770 ;
        RECT 141.870 222.480 142.870 222.770 ;
        RECT 143.710 222.480 144.710 222.770 ;
        RECT 145.550 222.480 146.550 222.770 ;
        RECT 147.390 222.480 148.390 222.770 ;
        RECT 149.230 222.480 150.230 222.770 ;
        RECT 151.070 222.480 152.070 222.770 ;
        RECT 152.910 222.480 153.910 222.770 ;
        RECT 154.750 222.480 155.750 222.770 ;
        RECT 156.590 222.480 157.590 222.770 ;
        RECT 158.430 222.480 159.430 222.770 ;
        RECT 160.270 222.480 161.270 222.770 ;
        RECT 162.110 222.480 163.110 222.770 ;
        RECT 163.950 222.480 164.950 222.770 ;
        RECT 165.790 222.480 166.790 222.770 ;
        RECT 167.630 222.480 168.630 222.770 ;
        RECT 169.470 222.480 170.470 222.770 ;
        RECT 171.310 222.480 172.310 222.770 ;
        RECT 173.150 222.480 174.150 222.770 ;
        RECT 174.990 222.480 175.990 222.770 ;
        RECT 176.830 222.480 177.830 222.770 ;
        RECT 178.670 222.480 179.670 222.770 ;
        RECT 180.510 222.480 181.510 222.770 ;
        RECT 182.350 222.480 183.350 222.770 ;
        RECT 184.190 222.480 185.190 222.770 ;
        RECT 186.030 222.480 187.030 222.770 ;
        RECT 187.870 222.480 188.870 222.770 ;
        RECT 189.710 222.480 190.710 222.770 ;
        RECT 191.550 222.480 192.550 222.770 ;
        RECT 193.390 222.480 194.390 222.770 ;
        RECT 195.230 222.480 196.230 222.770 ;
        RECT 197.070 222.480 198.070 222.770 ;
        RECT 198.910 222.480 199.910 222.770 ;
        RECT 200.750 222.480 201.750 222.770 ;
        RECT 202.590 222.480 203.590 222.770 ;
        RECT 204.430 222.480 205.430 222.770 ;
        RECT 206.270 222.480 207.270 222.770 ;
        RECT 208.110 222.480 209.110 222.770 ;
        RECT 209.950 222.480 210.950 222.770 ;
        RECT 211.790 222.480 212.790 222.770 ;
        RECT 213.630 222.480 214.630 222.770 ;
        RECT 215.470 222.480 216.470 222.770 ;
        RECT 217.310 222.480 218.310 222.770 ;
        RECT 219.150 222.480 220.150 222.770 ;
        RECT 220.990 222.480 221.990 222.770 ;
        RECT 222.830 222.480 223.830 222.770 ;
        RECT 224.670 222.480 225.670 222.770 ;
        RECT 226.510 222.480 227.510 222.770 ;
        RECT 228.350 222.480 229.350 222.770 ;
        RECT 230.190 222.480 231.190 222.770 ;
        RECT 232.030 222.480 233.030 222.770 ;
        RECT 233.870 222.480 234.870 222.770 ;
        RECT 235.710 222.480 236.710 222.770 ;
        RECT 237.550 222.480 238.550 222.770 ;
        RECT 239.390 222.480 240.390 222.770 ;
        RECT 241.230 222.480 242.230 222.770 ;
        RECT 243.070 222.480 251.530 222.770 ;
        RECT 0.550 0.560 251.530 222.480 ;
        RECT 0.550 0.270 8.550 0.560 ;
        RECT 9.390 0.270 10.390 0.560 ;
        RECT 11.230 0.270 12.230 0.560 ;
        RECT 13.070 0.270 14.070 0.560 ;
        RECT 14.910 0.270 15.910 0.560 ;
        RECT 16.750 0.270 17.750 0.560 ;
        RECT 18.590 0.270 19.590 0.560 ;
        RECT 20.430 0.270 21.430 0.560 ;
        RECT 22.270 0.270 23.270 0.560 ;
        RECT 24.110 0.270 25.110 0.560 ;
        RECT 25.950 0.270 26.950 0.560 ;
        RECT 27.790 0.270 28.790 0.560 ;
        RECT 29.630 0.270 30.630 0.560 ;
        RECT 31.470 0.270 32.470 0.560 ;
        RECT 33.310 0.270 34.310 0.560 ;
        RECT 35.150 0.270 36.150 0.560 ;
        RECT 36.990 0.270 37.990 0.560 ;
        RECT 38.830 0.270 39.830 0.560 ;
        RECT 40.670 0.270 41.670 0.560 ;
        RECT 42.510 0.270 43.510 0.560 ;
        RECT 44.350 0.270 45.350 0.560 ;
        RECT 46.190 0.270 47.190 0.560 ;
        RECT 48.030 0.270 49.030 0.560 ;
        RECT 49.870 0.270 50.870 0.560 ;
        RECT 51.710 0.270 52.710 0.560 ;
        RECT 53.550 0.270 54.550 0.560 ;
        RECT 55.390 0.270 56.390 0.560 ;
        RECT 57.230 0.270 58.230 0.560 ;
        RECT 59.070 0.270 60.070 0.560 ;
        RECT 60.910 0.270 61.910 0.560 ;
        RECT 62.750 0.270 63.750 0.560 ;
        RECT 64.590 0.270 65.590 0.560 ;
        RECT 66.430 0.270 67.430 0.560 ;
        RECT 68.270 0.270 69.270 0.560 ;
        RECT 70.110 0.270 71.110 0.560 ;
        RECT 71.950 0.270 72.950 0.560 ;
        RECT 73.790 0.270 74.790 0.560 ;
        RECT 75.630 0.270 76.630 0.560 ;
        RECT 77.470 0.270 78.470 0.560 ;
        RECT 79.310 0.270 80.310 0.560 ;
        RECT 81.150 0.270 82.150 0.560 ;
        RECT 82.990 0.270 83.990 0.560 ;
        RECT 84.830 0.270 85.830 0.560 ;
        RECT 86.670 0.270 87.670 0.560 ;
        RECT 88.510 0.270 89.510 0.560 ;
        RECT 90.350 0.270 91.350 0.560 ;
        RECT 92.190 0.270 93.190 0.560 ;
        RECT 94.030 0.270 95.030 0.560 ;
        RECT 95.870 0.270 96.870 0.560 ;
        RECT 97.710 0.270 98.710 0.560 ;
        RECT 99.550 0.270 100.550 0.560 ;
        RECT 101.390 0.270 102.390 0.560 ;
        RECT 103.230 0.270 104.230 0.560 ;
        RECT 105.070 0.270 106.070 0.560 ;
        RECT 106.910 0.270 107.910 0.560 ;
        RECT 108.750 0.270 109.750 0.560 ;
        RECT 110.590 0.270 111.590 0.560 ;
        RECT 112.430 0.270 113.430 0.560 ;
        RECT 114.270 0.270 115.270 0.560 ;
        RECT 116.110 0.270 117.110 0.560 ;
        RECT 117.950 0.270 118.950 0.560 ;
        RECT 119.790 0.270 120.790 0.560 ;
        RECT 121.630 0.270 122.630 0.560 ;
        RECT 123.470 0.270 124.470 0.560 ;
        RECT 125.310 0.270 126.310 0.560 ;
        RECT 127.150 0.270 128.150 0.560 ;
        RECT 128.990 0.270 129.990 0.560 ;
        RECT 130.830 0.270 131.830 0.560 ;
        RECT 132.670 0.270 133.670 0.560 ;
        RECT 134.510 0.270 135.510 0.560 ;
        RECT 136.350 0.270 137.350 0.560 ;
        RECT 138.190 0.270 139.190 0.560 ;
        RECT 140.030 0.270 141.030 0.560 ;
        RECT 141.870 0.270 142.870 0.560 ;
        RECT 143.710 0.270 144.710 0.560 ;
        RECT 145.550 0.270 146.550 0.560 ;
        RECT 147.390 0.270 148.390 0.560 ;
        RECT 149.230 0.270 150.230 0.560 ;
        RECT 151.070 0.270 152.070 0.560 ;
        RECT 152.910 0.270 153.910 0.560 ;
        RECT 154.750 0.270 155.750 0.560 ;
        RECT 156.590 0.270 157.590 0.560 ;
        RECT 158.430 0.270 159.430 0.560 ;
        RECT 160.270 0.270 161.270 0.560 ;
        RECT 162.110 0.270 163.110 0.560 ;
        RECT 163.950 0.270 164.950 0.560 ;
        RECT 165.790 0.270 166.790 0.560 ;
        RECT 167.630 0.270 168.630 0.560 ;
        RECT 169.470 0.270 170.470 0.560 ;
        RECT 171.310 0.270 172.310 0.560 ;
        RECT 173.150 0.270 174.150 0.560 ;
        RECT 174.990 0.270 175.990 0.560 ;
        RECT 176.830 0.270 177.830 0.560 ;
        RECT 178.670 0.270 179.670 0.560 ;
        RECT 180.510 0.270 181.510 0.560 ;
        RECT 182.350 0.270 183.350 0.560 ;
        RECT 184.190 0.270 185.190 0.560 ;
        RECT 186.030 0.270 187.030 0.560 ;
        RECT 187.870 0.270 188.870 0.560 ;
        RECT 189.710 0.270 190.710 0.560 ;
        RECT 191.550 0.270 192.550 0.560 ;
        RECT 193.390 0.270 194.390 0.560 ;
        RECT 195.230 0.270 196.230 0.560 ;
        RECT 197.070 0.270 198.070 0.560 ;
        RECT 198.910 0.270 199.910 0.560 ;
        RECT 200.750 0.270 201.750 0.560 ;
        RECT 202.590 0.270 203.590 0.560 ;
        RECT 204.430 0.270 205.430 0.560 ;
        RECT 206.270 0.270 207.270 0.560 ;
        RECT 208.110 0.270 209.110 0.560 ;
        RECT 209.950 0.270 210.950 0.560 ;
        RECT 211.790 0.270 212.790 0.560 ;
        RECT 213.630 0.270 214.630 0.560 ;
        RECT 215.470 0.270 216.470 0.560 ;
        RECT 217.310 0.270 218.310 0.560 ;
        RECT 219.150 0.270 220.150 0.560 ;
        RECT 220.990 0.270 221.990 0.560 ;
        RECT 222.830 0.270 223.830 0.560 ;
        RECT 224.670 0.270 225.670 0.560 ;
        RECT 226.510 0.270 227.510 0.560 ;
        RECT 228.350 0.270 229.350 0.560 ;
        RECT 230.190 0.270 231.190 0.560 ;
        RECT 232.030 0.270 233.030 0.560 ;
        RECT 233.870 0.270 234.870 0.560 ;
        RECT 235.710 0.270 236.710 0.560 ;
        RECT 237.550 0.270 238.550 0.560 ;
        RECT 239.390 0.270 240.390 0.560 ;
        RECT 241.230 0.270 242.230 0.560 ;
        RECT 243.070 0.270 251.530 0.560 ;
      LAYER met3 ;
        RECT 0.600 198.240 251.480 222.185 ;
        RECT 1.000 24.120 251.080 198.240 ;
        RECT 0.600 1.535 251.480 24.120 ;
      LAYER met4 ;
        RECT 0.310 1.535 6.560 218.785 ;
        RECT 8.960 1.535 11.860 218.785 ;
        RECT 14.260 1.535 36.560 218.785 ;
        RECT 38.960 1.535 41.860 218.785 ;
        RECT 44.260 1.535 66.560 218.785 ;
        RECT 68.960 1.535 71.860 218.785 ;
        RECT 74.260 1.535 96.560 218.785 ;
        RECT 98.960 1.535 101.860 218.785 ;
        RECT 104.260 1.535 126.560 218.785 ;
        RECT 128.960 1.535 131.860 218.785 ;
        RECT 134.260 1.535 156.560 218.785 ;
        RECT 158.960 1.535 161.860 218.785 ;
        RECT 164.260 1.535 186.560 218.785 ;
        RECT 188.960 1.535 191.860 218.785 ;
        RECT 194.260 1.535 216.560 218.785 ;
        RECT 218.960 1.535 221.860 218.785 ;
        RECT 224.260 1.535 244.425 218.785 ;
  END
END RegFile
END LIBRARY

